VERSION 5.7 ;
BUSBITCHARS "[]" ;
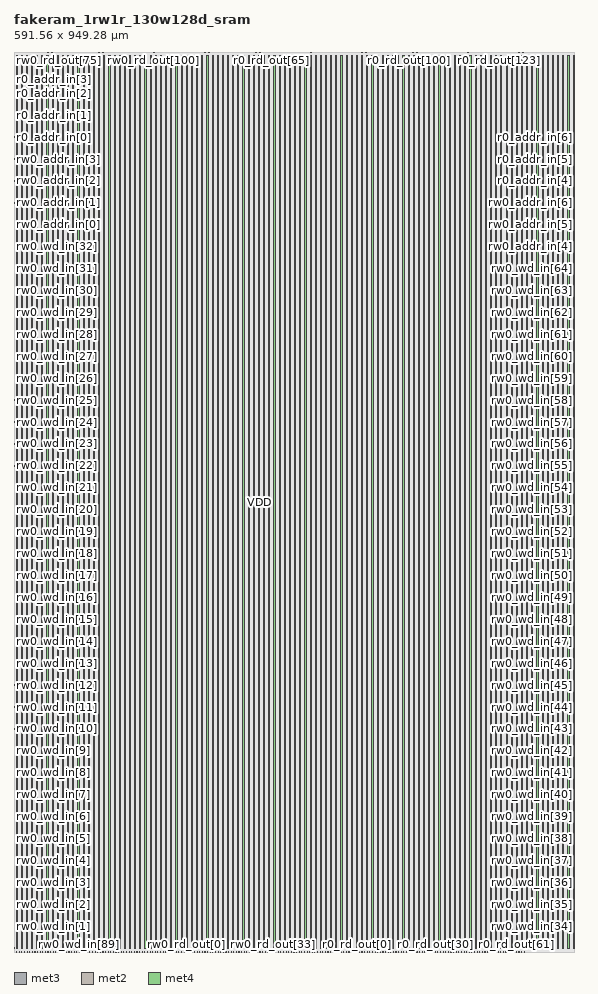
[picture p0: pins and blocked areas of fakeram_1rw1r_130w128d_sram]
MACRO fakeram_1rw1r_130w128d_sram
  FOREIGN fakeram_1rw1r_130w128d_sram 0 0 ;
  SYMMETRY X Y R90 ;
  SIZE 591.560 BY 949.280 ;
  CLASS BLOCK ;
  PIN rw0_wd_in[0]
    DIRECTION INPUT ;
    USE SIGNAL ;
    SHAPE ABUTMENT ;
    PORT
      LAYER met3 ;
      RECT 0.000 3.930 0.900 4.230 ;
    END
  END rw0_wd_in[0]
  PIN rw0_wd_in[1]
    DIRECTION INPUT ;
    USE SIGNAL ;
    SHAPE ABUTMENT ;
    PORT
      LAYER met3 ;
      RECT 0.000 27.050 0.900 27.350 ;
    END
  END rw0_wd_in[1]
  PIN rw0_wd_in[2]
    DIRECTION INPUT ;
    USE SIGNAL ;
    SHAPE ABUTMENT ;
    PORT
      LAYER met3 ;
      RECT 0.000 50.170 0.900 50.470 ;
    END
  END rw0_wd_in[2]
  PIN rw0_wd_in[3]
    DIRECTION INPUT ;
    USE SIGNAL ;
    SHAPE ABUTMENT ;
    PORT
      LAYER met3 ;
      RECT 0.000 73.290 0.900 73.590 ;
    END
  END rw0_wd_in[3]
  PIN rw0_wd_in[4]
    DIRECTION INPUT ;
    USE SIGNAL ;
    SHAPE ABUTMENT ;
    PORT
      LAYER met3 ;
      RECT 0.000 96.410 0.900 96.710 ;
    END
  END rw0_wd_in[4]
  PIN rw0_wd_in[5]
    DIRECTION INPUT ;
    USE SIGNAL ;
    SHAPE ABUTMENT ;
    PORT
      LAYER met3 ;
      RECT 0.000 119.530 0.900 119.830 ;
    END
  END rw0_wd_in[5]
  PIN rw0_wd_in[6]
    DIRECTION INPUT ;
    USE SIGNAL ;
    SHAPE ABUTMENT ;
    PORT
      LAYER met3 ;
      RECT 0.000 142.650 0.900 142.950 ;
    END
  END rw0_wd_in[6]
  PIN rw0_wd_in[7]
    DIRECTION INPUT ;
    USE SIGNAL ;
    SHAPE ABUTMENT ;
    PORT
      LAYER met3 ;
      RECT 0.000 165.770 0.900 166.070 ;
    END
  END rw0_wd_in[7]
  PIN rw0_wd_in[8]
    DIRECTION INPUT ;
    USE SIGNAL ;
    SHAPE ABUTMENT ;
    PORT
      LAYER met3 ;
      RECT 0.000 188.890 0.900 189.190 ;
    END
  END rw0_wd_in[8]
  PIN rw0_wd_in[9]
    DIRECTION INPUT ;
    USE SIGNAL ;
    SHAPE ABUTMENT ;
    PORT
      LAYER met3 ;
      RECT 0.000 212.010 0.900 212.310 ;
    END
  END rw0_wd_in[9]
  PIN rw0_wd_in[10]
    DIRECTION INPUT ;
    USE SIGNAL ;
    SHAPE ABUTMENT ;
    PORT
      LAYER met3 ;
      RECT 0.000 235.130 0.900 235.430 ;
    END
  END rw0_wd_in[10]
  PIN rw0_wd_in[11]
    DIRECTION INPUT ;
    USE SIGNAL ;
    SHAPE ABUTMENT ;
    PORT
      LAYER met3 ;
      RECT 0.000 258.250 0.900 258.550 ;
    END
  END rw0_wd_in[11]
  PIN rw0_wd_in[12]
    DIRECTION INPUT ;
    USE SIGNAL ;
    SHAPE ABUTMENT ;
    PORT
      LAYER met3 ;
      RECT 0.000 281.370 0.900 281.670 ;
    END
  END rw0_wd_in[12]
  PIN rw0_wd_in[13]
    DIRECTION INPUT ;
    USE SIGNAL ;
    SHAPE ABUTMENT ;
    PORT
      LAYER met3 ;
      RECT 0.000 304.490 0.900 304.790 ;
    END
  END rw0_wd_in[13]
  PIN rw0_wd_in[14]
    DIRECTION INPUT ;
    USE SIGNAL ;
    SHAPE ABUTMENT ;
    PORT
      LAYER met3 ;
      RECT 0.000 327.610 0.900 327.910 ;
    END
  END rw0_wd_in[14]
  PIN rw0_wd_in[15]
    DIRECTION INPUT ;
    USE SIGNAL ;
    SHAPE ABUTMENT ;
    PORT
      LAYER met3 ;
      RECT 0.000 350.730 0.900 351.030 ;
    END
  END rw0_wd_in[15]
  PIN rw0_wd_in[16]
    DIRECTION INPUT ;
    USE SIGNAL ;
    SHAPE ABUTMENT ;
    PORT
      LAYER met3 ;
      RECT 0.000 373.850 0.900 374.150 ;
    END
  END rw0_wd_in[16]
  PIN rw0_wd_in[17]
    DIRECTION INPUT ;
    USE SIGNAL ;
    SHAPE ABUTMENT ;
    PORT
      LAYER met3 ;
      RECT 0.000 396.970 0.900 397.270 ;
    END
  END rw0_wd_in[17]
  PIN rw0_wd_in[18]
    DIRECTION INPUT ;
    USE SIGNAL ;
    SHAPE ABUTMENT ;
    PORT
      LAYER met3 ;
      RECT 0.000 420.090 0.900 420.390 ;
    END
  END rw0_wd_in[18]
  PIN rw0_wd_in[19]
    DIRECTION INPUT ;
    USE SIGNAL ;
    SHAPE ABUTMENT ;
    PORT
      LAYER met3 ;
      RECT 0.000 443.210 0.900 443.510 ;
    END
  END rw0_wd_in[19]
  PIN rw0_wd_in[20]
    DIRECTION INPUT ;
    USE SIGNAL ;
    SHAPE ABUTMENT ;
    PORT
      LAYER met3 ;
      RECT 0.000 466.330 0.900 466.630 ;
    END
  END rw0_wd_in[20]
  PIN rw0_wd_in[21]
    DIRECTION INPUT ;
    USE SIGNAL ;
    SHAPE ABUTMENT ;
    PORT
      LAYER met3 ;
      RECT 0.000 489.450 0.900 489.750 ;
    END
  END rw0_wd_in[21]
  PIN rw0_wd_in[22]
    DIRECTION INPUT ;
    USE SIGNAL ;
    SHAPE ABUTMENT ;
    PORT
      LAYER met3 ;
      RECT 0.000 512.570 0.900 512.870 ;
    END
  END rw0_wd_in[22]
  PIN rw0_wd_in[23]
    DIRECTION INPUT ;
    USE SIGNAL ;
    SHAPE ABUTMENT ;
    PORT
      LAYER met3 ;
      RECT 0.000 535.690 0.900 535.990 ;
    END
  END rw0_wd_in[23]
  PIN rw0_wd_in[24]
    DIRECTION INPUT ;
    USE SIGNAL ;
    SHAPE ABUTMENT ;
    PORT
      LAYER met3 ;
      RECT 0.000 558.810 0.900 559.110 ;
    END
  END rw0_wd_in[24]
  PIN rw0_wd_in[25]
    DIRECTION INPUT ;
    USE SIGNAL ;
    SHAPE ABUTMENT ;
    PORT
      LAYER met3 ;
      RECT 0.000 581.930 0.900 582.230 ;
    END
  END rw0_wd_in[25]
  PIN rw0_wd_in[26]
    DIRECTION INPUT ;
    USE SIGNAL ;
    SHAPE ABUTMENT ;
    PORT
      LAYER met3 ;
      RECT 0.000 605.050 0.900 605.350 ;
    END
  END rw0_wd_in[26]
  PIN rw0_wd_in[27]
    DIRECTION INPUT ;
    USE SIGNAL ;
    SHAPE ABUTMENT ;
    PORT
      LAYER met3 ;
      RECT 0.000 628.170 0.900 628.470 ;
    END
  END rw0_wd_in[27]
  PIN rw0_wd_in[28]
    DIRECTION INPUT ;
    USE SIGNAL ;
    SHAPE ABUTMENT ;
    PORT
      LAYER met3 ;
      RECT 0.000 651.290 0.900 651.590 ;
    END
  END rw0_wd_in[28]
  PIN rw0_wd_in[29]
    DIRECTION INPUT ;
    USE SIGNAL ;
    SHAPE ABUTMENT ;
    PORT
      LAYER met3 ;
      RECT 0.000 674.410 0.900 674.710 ;
    END
  END rw0_wd_in[29]
  PIN rw0_wd_in[30]
    DIRECTION INPUT ;
    USE SIGNAL ;
    SHAPE ABUTMENT ;
    PORT
      LAYER met3 ;
      RECT 0.000 697.530 0.900 697.830 ;
    END
  END rw0_wd_in[30]
  PIN rw0_wd_in[31]
    DIRECTION INPUT ;
    USE SIGNAL ;
    SHAPE ABUTMENT ;
    PORT
      LAYER met3 ;
      RECT 0.000 720.650 0.900 720.950 ;
    END
  END rw0_wd_in[31]
  PIN rw0_wd_in[32]
    DIRECTION INPUT ;
    USE SIGNAL ;
    SHAPE ABUTMENT ;
    PORT
      LAYER met3 ;
      RECT 0.000 743.770 0.900 744.070 ;
    END
  END rw0_wd_in[32]
  PIN rw0_wd_in[33]
    DIRECTION INPUT ;
    USE SIGNAL ;
    SHAPE ABUTMENT ;
    PORT
      LAYER met3 ;
      RECT 590.660 3.930 591.560 4.230 ;
    END
  END rw0_wd_in[33]
  PIN rw0_wd_in[34]
    DIRECTION INPUT ;
    USE SIGNAL ;
    SHAPE ABUTMENT ;
    PORT
      LAYER met3 ;
      RECT 590.660 27.050 591.560 27.350 ;
    END
  END rw0_wd_in[34]
  PIN rw0_wd_in[35]
    DIRECTION INPUT ;
    USE SIGNAL ;
    SHAPE ABUTMENT ;
    PORT
      LAYER met3 ;
      RECT 590.660 50.170 591.560 50.470 ;
    END
  END rw0_wd_in[35]
  PIN rw0_wd_in[36]
    DIRECTION INPUT ;
    USE SIGNAL ;
    SHAPE ABUTMENT ;
    PORT
      LAYER met3 ;
      RECT 590.660 73.290 591.560 73.590 ;
    END
  END rw0_wd_in[36]
  PIN rw0_wd_in[37]
    DIRECTION INPUT ;
    USE SIGNAL ;
    SHAPE ABUTMENT ;
    PORT
      LAYER met3 ;
      RECT 590.660 96.410 591.560 96.710 ;
    END
  END rw0_wd_in[37]
  PIN rw0_wd_in[38]
    DIRECTION INPUT ;
    USE SIGNAL ;
    SHAPE ABUTMENT ;
    PORT
      LAYER met3 ;
      RECT 590.660 119.530 591.560 119.830 ;
    END
  END rw0_wd_in[38]
  PIN rw0_wd_in[39]
    DIRECTION INPUT ;
    USE SIGNAL ;
    SHAPE ABUTMENT ;
    PORT
      LAYER met3 ;
      RECT 590.660 142.650 591.560 142.950 ;
    END
  END rw0_wd_in[39]
  PIN rw0_wd_in[40]
    DIRECTION INPUT ;
    USE SIGNAL ;
    SHAPE ABUTMENT ;
    PORT
      LAYER met3 ;
      RECT 590.660 165.770 591.560 166.070 ;
    END
  END rw0_wd_in[40]
  PIN rw0_wd_in[41]
    DIRECTION INPUT ;
    USE SIGNAL ;
    SHAPE ABUTMENT ;
    PORT
      LAYER met3 ;
      RECT 590.660 188.890 591.560 189.190 ;
    END
  END rw0_wd_in[41]
  PIN rw0_wd_in[42]
    DIRECTION INPUT ;
    USE SIGNAL ;
    SHAPE ABUTMENT ;
    PORT
      LAYER met3 ;
      RECT 590.660 212.010 591.560 212.310 ;
    END
  END rw0_wd_in[42]
  PIN rw0_wd_in[43]
    DIRECTION INPUT ;
    USE SIGNAL ;
    SHAPE ABUTMENT ;
    PORT
      LAYER met3 ;
      RECT 590.660 235.130 591.560 235.430 ;
    END
  END rw0_wd_in[43]
  PIN rw0_wd_in[44]
    DIRECTION INPUT ;
    USE SIGNAL ;
    SHAPE ABUTMENT ;
    PORT
      LAYER met3 ;
      RECT 590.660 258.250 591.560 258.550 ;
    END
  END rw0_wd_in[44]
  PIN rw0_wd_in[45]
    DIRECTION INPUT ;
    USE SIGNAL ;
    SHAPE ABUTMENT ;
    PORT
      LAYER met3 ;
      RECT 590.660 281.370 591.560 281.670 ;
    END
  END rw0_wd_in[45]
  PIN rw0_wd_in[46]
    DIRECTION INPUT ;
    USE SIGNAL ;
    SHAPE ABUTMENT ;
    PORT
      LAYER met3 ;
      RECT 590.660 304.490 591.560 304.790 ;
    END
  END rw0_wd_in[46]
  PIN rw0_wd_in[47]
    DIRECTION INPUT ;
    USE SIGNAL ;
    SHAPE ABUTMENT ;
    PORT
      LAYER met3 ;
      RECT 590.660 327.610 591.560 327.910 ;
    END
  END rw0_wd_in[47]
  PIN rw0_wd_in[48]
    DIRECTION INPUT ;
    USE SIGNAL ;
    SHAPE ABUTMENT ;
    PORT
      LAYER met3 ;
      RECT 590.660 350.730 591.560 351.030 ;
    END
  END rw0_wd_in[48]
  PIN rw0_wd_in[49]
    DIRECTION INPUT ;
    USE SIGNAL ;
    SHAPE ABUTMENT ;
    PORT
      LAYER met3 ;
      RECT 590.660 373.850 591.560 374.150 ;
    END
  END rw0_wd_in[49]
  PIN rw0_wd_in[50]
    DIRECTION INPUT ;
    USE SIGNAL ;
    SHAPE ABUTMENT ;
    PORT
      LAYER met3 ;
      RECT 590.660 396.970 591.560 397.270 ;
    END
  END rw0_wd_in[50]
  PIN rw0_wd_in[51]
    DIRECTION INPUT ;
    USE SIGNAL ;
    SHAPE ABUTMENT ;
    PORT
      LAYER met3 ;
      RECT 590.660 420.090 591.560 420.390 ;
    END
  END rw0_wd_in[51]
  PIN rw0_wd_in[52]
    DIRECTION INPUT ;
    USE SIGNAL ;
    SHAPE ABUTMENT ;
    PORT
      LAYER met3 ;
      RECT 590.660 443.210 591.560 443.510 ;
    END
  END rw0_wd_in[52]
  PIN rw0_wd_in[53]
    DIRECTION INPUT ;
    USE SIGNAL ;
    SHAPE ABUTMENT ;
    PORT
      LAYER met3 ;
      RECT 590.660 466.330 591.560 466.630 ;
    END
  END rw0_wd_in[53]
  PIN rw0_wd_in[54]
    DIRECTION INPUT ;
    USE SIGNAL ;
    SHAPE ABUTMENT ;
    PORT
      LAYER met3 ;
      RECT 590.660 489.450 591.560 489.750 ;
    END
  END rw0_wd_in[54]
  PIN rw0_wd_in[55]
    DIRECTION INPUT ;
    USE SIGNAL ;
    SHAPE ABUTMENT ;
    PORT
      LAYER met3 ;
      RECT 590.660 512.570 591.560 512.870 ;
    END
  END rw0_wd_in[55]
  PIN rw0_wd_in[56]
    DIRECTION INPUT ;
    USE SIGNAL ;
    SHAPE ABUTMENT ;
    PORT
      LAYER met3 ;
      RECT 590.660 535.690 591.560 535.990 ;
    END
  END rw0_wd_in[56]
  PIN rw0_wd_in[57]
    DIRECTION INPUT ;
    USE SIGNAL ;
    SHAPE ABUTMENT ;
    PORT
      LAYER met3 ;
      RECT 590.660 558.810 591.560 559.110 ;
    END
  END rw0_wd_in[57]
  PIN rw0_wd_in[58]
    DIRECTION INPUT ;
    USE SIGNAL ;
    SHAPE ABUTMENT ;
    PORT
      LAYER met3 ;
      RECT 590.660 581.930 591.560 582.230 ;
    END
  END rw0_wd_in[58]
  PIN rw0_wd_in[59]
    DIRECTION INPUT ;
    USE SIGNAL ;
    SHAPE ABUTMENT ;
    PORT
      LAYER met3 ;
      RECT 590.660 605.050 591.560 605.350 ;
    END
  END rw0_wd_in[59]
  PIN rw0_wd_in[60]
    DIRECTION INPUT ;
    USE SIGNAL ;
    SHAPE ABUTMENT ;
    PORT
      LAYER met3 ;
      RECT 590.660 628.170 591.560 628.470 ;
    END
  END rw0_wd_in[60]
  PIN rw0_wd_in[61]
    DIRECTION INPUT ;
    USE SIGNAL ;
    SHAPE ABUTMENT ;
    PORT
      LAYER met3 ;
      RECT 590.660 651.290 591.560 651.590 ;
    END
  END rw0_wd_in[61]
  PIN rw0_wd_in[62]
    DIRECTION INPUT ;
    USE SIGNAL ;
    SHAPE ABUTMENT ;
    PORT
      LAYER met3 ;
      RECT 590.660 674.410 591.560 674.710 ;
    END
  END rw0_wd_in[62]
  PIN rw0_wd_in[63]
    DIRECTION INPUT ;
    USE SIGNAL ;
    SHAPE ABUTMENT ;
    PORT
      LAYER met3 ;
      RECT 590.660 697.530 591.560 697.830 ;
    END
  END rw0_wd_in[63]
  PIN rw0_wd_in[64]
    DIRECTION INPUT ;
    USE SIGNAL ;
    SHAPE ABUTMENT ;
    PORT
      LAYER met3 ;
      RECT 590.660 720.650 591.560 720.950 ;
    END
  END rw0_wd_in[64]
  PIN rw0_wd_in[65]
    DIRECTION INPUT ;
    USE SIGNAL ;
    SHAPE ABUTMENT ;
    PORT
      LAYER met2 ;
      RECT 2.690 0.000 2.830 0.420 ;
    END
  END rw0_wd_in[65]
  PIN rw0_wd_in[66]
    DIRECTION INPUT ;
    USE SIGNAL ;
    SHAPE ABUTMENT ;
    PORT
      LAYER met2 ;
      RECT 5.450 0.000 5.590 0.420 ;
    END
  END rw0_wd_in[66]
  PIN rw0_wd_in[67]
    DIRECTION INPUT ;
    USE SIGNAL ;
    SHAPE ABUTMENT ;
    PORT
      LAYER met2 ;
      RECT 8.210 0.000 8.350 0.420 ;
    END
  END rw0_wd_in[67]
  PIN rw0_wd_in[68]
    DIRECTION INPUT ;
    USE SIGNAL ;
    SHAPE ABUTMENT ;
    PORT
      LAYER met2 ;
      RECT 10.970 0.000 11.110 0.420 ;
    END
  END rw0_wd_in[68]
  PIN rw0_wd_in[69]
    DIRECTION INPUT ;
    USE SIGNAL ;
    SHAPE ABUTMENT ;
    PORT
      LAYER met2 ;
      RECT 13.730 0.000 13.870 0.420 ;
    END
  END rw0_wd_in[69]
  PIN rw0_wd_in[70]
    DIRECTION INPUT ;
    USE SIGNAL ;
    SHAPE ABUTMENT ;
    PORT
      LAYER met2 ;
      RECT 16.490 0.000 16.630 0.420 ;
    END
  END rw0_wd_in[70]
  PIN rw0_wd_in[71]
    DIRECTION INPUT ;
    USE SIGNAL ;
    SHAPE ABUTMENT ;
    PORT
      LAYER met2 ;
      RECT 19.250 0.000 19.390 0.420 ;
    END
  END rw0_wd_in[71]
  PIN rw0_wd_in[72]
    DIRECTION INPUT ;
    USE SIGNAL ;
    SHAPE ABUTMENT ;
    PORT
      LAYER met2 ;
      RECT 22.010 0.000 22.150 0.420 ;
    END
  END rw0_wd_in[72]
  PIN rw0_wd_in[73]
    DIRECTION INPUT ;
    USE SIGNAL ;
    SHAPE ABUTMENT ;
    PORT
      LAYER met2 ;
      RECT 24.770 0.000 24.910 0.420 ;
    END
  END rw0_wd_in[73]
  PIN rw0_wd_in[74]
    DIRECTION INPUT ;
    USE SIGNAL ;
    SHAPE ABUTMENT ;
    PORT
      LAYER met2 ;
      RECT 27.530 0.000 27.670 0.420 ;
    END
  END rw0_wd_in[74]
  PIN rw0_wd_in[75]
    DIRECTION INPUT ;
    USE SIGNAL ;
    SHAPE ABUTMENT ;
    PORT
      LAYER met2 ;
      RECT 30.290 0.000 30.430 0.420 ;
    END
  END rw0_wd_in[75]
  PIN rw0_wd_in[76]
    DIRECTION INPUT ;
    USE SIGNAL ;
    SHAPE ABUTMENT ;
    PORT
      LAYER met2 ;
      RECT 33.050 0.000 33.190 0.420 ;
    END
  END rw0_wd_in[76]
  PIN rw0_wd_in[77]
    DIRECTION INPUT ;
    USE SIGNAL ;
    SHAPE ABUTMENT ;
    PORT
      LAYER met2 ;
      RECT 35.810 0.000 35.950 0.420 ;
    END
  END rw0_wd_in[77]
  PIN rw0_wd_in[78]
    DIRECTION INPUT ;
    USE SIGNAL ;
    SHAPE ABUTMENT ;
    PORT
      LAYER met2 ;
      RECT 38.570 0.000 38.710 0.420 ;
    END
  END rw0_wd_in[78]
  PIN rw0_wd_in[79]
    DIRECTION INPUT ;
    USE SIGNAL ;
    SHAPE ABUTMENT ;
    PORT
      LAYER met2 ;
      RECT 41.330 0.000 41.470 0.420 ;
    END
  END rw0_wd_in[79]
  PIN rw0_wd_in[80]
    DIRECTION INPUT ;
    USE SIGNAL ;
    SHAPE ABUTMENT ;
    PORT
      LAYER met2 ;
      RECT 44.090 0.000 44.230 0.420 ;
    END
  END rw0_wd_in[80]
  PIN rw0_wd_in[81]
    DIRECTION INPUT ;
    USE SIGNAL ;
    SHAPE ABUTMENT ;
    PORT
      LAYER met2 ;
      RECT 46.850 0.000 46.990 0.420 ;
    END
  END rw0_wd_in[81]
  PIN rw0_wd_in[82]
    DIRECTION INPUT ;
    USE SIGNAL ;
    SHAPE ABUTMENT ;
    PORT
      LAYER met2 ;
      RECT 49.610 0.000 49.750 0.420 ;
    END
  END rw0_wd_in[82]
  PIN rw0_wd_in[83]
    DIRECTION INPUT ;
    USE SIGNAL ;
    SHAPE ABUTMENT ;
    PORT
      LAYER met2 ;
      RECT 52.370 0.000 52.510 0.420 ;
    END
  END rw0_wd_in[83]
  PIN rw0_wd_in[84]
    DIRECTION INPUT ;
    USE SIGNAL ;
    SHAPE ABUTMENT ;
    PORT
      LAYER met2 ;
      RECT 55.130 0.000 55.270 0.420 ;
    END
  END rw0_wd_in[84]
  PIN rw0_wd_in[85]
    DIRECTION INPUT ;
    USE SIGNAL ;
    SHAPE ABUTMENT ;
    PORT
      LAYER met2 ;
      RECT 57.890 0.000 58.030 0.420 ;
    END
  END rw0_wd_in[85]
  PIN rw0_wd_in[86]
    DIRECTION INPUT ;
    USE SIGNAL ;
    SHAPE ABUTMENT ;
    PORT
      LAYER met2 ;
      RECT 60.650 0.000 60.790 0.420 ;
    END
  END rw0_wd_in[86]
  PIN rw0_wd_in[87]
    DIRECTION INPUT ;
    USE SIGNAL ;
    SHAPE ABUTMENT ;
    PORT
      LAYER met2 ;
      RECT 63.410 0.000 63.550 0.420 ;
    END
  END rw0_wd_in[87]
  PIN rw0_wd_in[88]
    DIRECTION INPUT ;
    USE SIGNAL ;
    SHAPE ABUTMENT ;
    PORT
      LAYER met2 ;
      RECT 66.170 0.000 66.310 0.420 ;
    END
  END rw0_wd_in[88]
  PIN rw0_wd_in[89]
    DIRECTION INPUT ;
    USE SIGNAL ;
    SHAPE ABUTMENT ;
    PORT
      LAYER met2 ;
      RECT 68.930 0.000 69.070 0.420 ;
    END
  END rw0_wd_in[89]
  PIN rw0_wd_in[90]
    DIRECTION INPUT ;
    USE SIGNAL ;
    SHAPE ABUTMENT ;
    PORT
      LAYER met2 ;
      RECT 71.690 0.000 71.830 0.420 ;
    END
  END rw0_wd_in[90]
  PIN rw0_wd_in[91]
    DIRECTION INPUT ;
    USE SIGNAL ;
    SHAPE ABUTMENT ;
    PORT
      LAYER met2 ;
      RECT 74.450 0.000 74.590 0.420 ;
    END
  END rw0_wd_in[91]
  PIN rw0_wd_in[92]
    DIRECTION INPUT ;
    USE SIGNAL ;
    SHAPE ABUTMENT ;
    PORT
      LAYER met2 ;
      RECT 77.210 0.000 77.350 0.420 ;
    END
  END rw0_wd_in[92]
  PIN rw0_wd_in[93]
    DIRECTION INPUT ;
    USE SIGNAL ;
    SHAPE ABUTMENT ;
    PORT
      LAYER met2 ;
      RECT 79.970 0.000 80.110 0.420 ;
    END
  END rw0_wd_in[93]
  PIN rw0_wd_in[94]
    DIRECTION INPUT ;
    USE SIGNAL ;
    SHAPE ABUTMENT ;
    PORT
      LAYER met2 ;
      RECT 82.730 0.000 82.870 0.420 ;
    END
  END rw0_wd_in[94]
  PIN rw0_wd_in[95]
    DIRECTION INPUT ;
    USE SIGNAL ;
    SHAPE ABUTMENT ;
    PORT
      LAYER met2 ;
      RECT 85.490 0.000 85.630 0.420 ;
    END
  END rw0_wd_in[95]
  PIN rw0_wd_in[96]
    DIRECTION INPUT ;
    USE SIGNAL ;
    SHAPE ABUTMENT ;
    PORT
      LAYER met2 ;
      RECT 88.250 0.000 88.390 0.420 ;
    END
  END rw0_wd_in[96]
  PIN rw0_wd_in[97]
    DIRECTION INPUT ;
    USE SIGNAL ;
    SHAPE ABUTMENT ;
    PORT
      LAYER met2 ;
      RECT 91.010 0.000 91.150 0.420 ;
    END
  END rw0_wd_in[97]
  PIN rw0_wd_in[98]
    DIRECTION INPUT ;
    USE SIGNAL ;
    SHAPE ABUTMENT ;
    PORT
      LAYER met2 ;
      RECT 93.770 0.000 93.910 0.420 ;
    END
  END rw0_wd_in[98]
  PIN rw0_wd_in[99]
    DIRECTION INPUT ;
    USE SIGNAL ;
    SHAPE ABUTMENT ;
    PORT
      LAYER met2 ;
      RECT 96.530 0.000 96.670 0.420 ;
    END
  END rw0_wd_in[99]
  PIN rw0_wd_in[100]
    DIRECTION INPUT ;
    USE SIGNAL ;
    SHAPE ABUTMENT ;
    PORT
      LAYER met2 ;
      RECT 99.290 0.000 99.430 0.420 ;
    END
  END rw0_wd_in[100]
  PIN rw0_wd_in[101]
    DIRECTION INPUT ;
    USE SIGNAL ;
    SHAPE ABUTMENT ;
    PORT
      LAYER met2 ;
      RECT 102.050 0.000 102.190 0.420 ;
    END
  END rw0_wd_in[101]
  PIN rw0_wd_in[102]
    DIRECTION INPUT ;
    USE SIGNAL ;
    SHAPE ABUTMENT ;
    PORT
      LAYER met2 ;
      RECT 104.810 0.000 104.950 0.420 ;
    END
  END rw0_wd_in[102]
  PIN rw0_wd_in[103]
    DIRECTION INPUT ;
    USE SIGNAL ;
    SHAPE ABUTMENT ;
    PORT
      LAYER met2 ;
      RECT 107.570 0.000 107.710 0.420 ;
    END
  END rw0_wd_in[103]
  PIN rw0_wd_in[104]
    DIRECTION INPUT ;
    USE SIGNAL ;
    SHAPE ABUTMENT ;
    PORT
      LAYER met2 ;
      RECT 110.330 0.000 110.470 0.420 ;
    END
  END rw0_wd_in[104]
  PIN rw0_wd_in[105]
    DIRECTION INPUT ;
    USE SIGNAL ;
    SHAPE ABUTMENT ;
    PORT
      LAYER met2 ;
      RECT 113.090 0.000 113.230 0.420 ;
    END
  END rw0_wd_in[105]
  PIN rw0_wd_in[106]
    DIRECTION INPUT ;
    USE SIGNAL ;
    SHAPE ABUTMENT ;
    PORT
      LAYER met2 ;
      RECT 115.850 0.000 115.990 0.420 ;
    END
  END rw0_wd_in[106]
  PIN rw0_wd_in[107]
    DIRECTION INPUT ;
    USE SIGNAL ;
    SHAPE ABUTMENT ;
    PORT
      LAYER met2 ;
      RECT 118.610 0.000 118.750 0.420 ;
    END
  END rw0_wd_in[107]
  PIN rw0_wd_in[108]
    DIRECTION INPUT ;
    USE SIGNAL ;
    SHAPE ABUTMENT ;
    PORT
      LAYER met2 ;
      RECT 121.370 0.000 121.510 0.420 ;
    END
  END rw0_wd_in[108]
  PIN rw0_wd_in[109]
    DIRECTION INPUT ;
    USE SIGNAL ;
    SHAPE ABUTMENT ;
    PORT
      LAYER met2 ;
      RECT 124.130 0.000 124.270 0.420 ;
    END
  END rw0_wd_in[109]
  PIN rw0_wd_in[110]
    DIRECTION INPUT ;
    USE SIGNAL ;
    SHAPE ABUTMENT ;
    PORT
      LAYER met2 ;
      RECT 126.890 0.000 127.030 0.420 ;
    END
  END rw0_wd_in[110]
  PIN rw0_wd_in[111]
    DIRECTION INPUT ;
    USE SIGNAL ;
    SHAPE ABUTMENT ;
    PORT
      LAYER met2 ;
      RECT 129.650 0.000 129.790 0.420 ;
    END
  END rw0_wd_in[111]
  PIN rw0_wd_in[112]
    DIRECTION INPUT ;
    USE SIGNAL ;
    SHAPE ABUTMENT ;
    PORT
      LAYER met2 ;
      RECT 132.410 0.000 132.550 0.420 ;
    END
  END rw0_wd_in[112]
  PIN rw0_wd_in[113]
    DIRECTION INPUT ;
    USE SIGNAL ;
    SHAPE ABUTMENT ;
    PORT
      LAYER met2 ;
      RECT 135.170 0.000 135.310 0.420 ;
    END
  END rw0_wd_in[113]
  PIN rw0_wd_in[114]
    DIRECTION INPUT ;
    USE SIGNAL ;
    SHAPE ABUTMENT ;
    PORT
      LAYER met2 ;
      RECT 137.930 0.000 138.070 0.420 ;
    END
  END rw0_wd_in[114]
  PIN rw0_wd_in[115]
    DIRECTION INPUT ;
    USE SIGNAL ;
    SHAPE ABUTMENT ;
    PORT
      LAYER met2 ;
      RECT 140.690 0.000 140.830 0.420 ;
    END
  END rw0_wd_in[115]
  PIN rw0_wd_in[116]
    DIRECTION INPUT ;
    USE SIGNAL ;
    SHAPE ABUTMENT ;
    PORT
      LAYER met2 ;
      RECT 143.450 0.000 143.590 0.420 ;
    END
  END rw0_wd_in[116]
  PIN rw0_wd_in[117]
    DIRECTION INPUT ;
    USE SIGNAL ;
    SHAPE ABUTMENT ;
    PORT
      LAYER met2 ;
      RECT 146.210 0.000 146.350 0.420 ;
    END
  END rw0_wd_in[117]
  PIN rw0_wd_in[118]
    DIRECTION INPUT ;
    USE SIGNAL ;
    SHAPE ABUTMENT ;
    PORT
      LAYER met2 ;
      RECT 148.970 0.000 149.110 0.420 ;
    END
  END rw0_wd_in[118]
  PIN rw0_wd_in[119]
    DIRECTION INPUT ;
    USE SIGNAL ;
    SHAPE ABUTMENT ;
    PORT
      LAYER met2 ;
      RECT 151.730 0.000 151.870 0.420 ;
    END
  END rw0_wd_in[119]
  PIN rw0_wd_in[120]
    DIRECTION INPUT ;
    USE SIGNAL ;
    SHAPE ABUTMENT ;
    PORT
      LAYER met2 ;
      RECT 154.490 0.000 154.630 0.420 ;
    END
  END rw0_wd_in[120]
  PIN rw0_wd_in[121]
    DIRECTION INPUT ;
    USE SIGNAL ;
    SHAPE ABUTMENT ;
    PORT
      LAYER met2 ;
      RECT 157.250 0.000 157.390 0.420 ;
    END
  END rw0_wd_in[121]
  PIN rw0_wd_in[122]
    DIRECTION INPUT ;
    USE SIGNAL ;
    SHAPE ABUTMENT ;
    PORT
      LAYER met2 ;
      RECT 160.010 0.000 160.150 0.420 ;
    END
  END rw0_wd_in[122]
  PIN rw0_wd_in[123]
    DIRECTION INPUT ;
    USE SIGNAL ;
    SHAPE ABUTMENT ;
    PORT
      LAYER met2 ;
      RECT 162.770 0.000 162.910 0.420 ;
    END
  END rw0_wd_in[123]
  PIN rw0_wd_in[124]
    DIRECTION INPUT ;
    USE SIGNAL ;
    SHAPE ABUTMENT ;
    PORT
      LAYER met2 ;
      RECT 165.530 0.000 165.670 0.420 ;
    END
  END rw0_wd_in[124]
  PIN rw0_wd_in[125]
    DIRECTION INPUT ;
    USE SIGNAL ;
    SHAPE ABUTMENT ;
    PORT
      LAYER met2 ;
      RECT 168.290 0.000 168.430 0.420 ;
    END
  END rw0_wd_in[125]
  PIN rw0_wd_in[126]
    DIRECTION INPUT ;
    USE SIGNAL ;
    SHAPE ABUTMENT ;
    PORT
      LAYER met2 ;
      RECT 171.050 0.000 171.190 0.420 ;
    END
  END rw0_wd_in[126]
  PIN rw0_wd_in[127]
    DIRECTION INPUT ;
    USE SIGNAL ;
    SHAPE ABUTMENT ;
    PORT
      LAYER met2 ;
      RECT 173.810 0.000 173.950 0.420 ;
    END
  END rw0_wd_in[127]
  PIN rw0_wd_in[128]
    DIRECTION INPUT ;
    USE SIGNAL ;
    SHAPE ABUTMENT ;
    PORT
      LAYER met2 ;
      RECT 176.570 0.000 176.710 0.420 ;
    END
  END rw0_wd_in[128]
  PIN rw0_wd_in[129]
    DIRECTION INPUT ;
    USE SIGNAL ;
    SHAPE ABUTMENT ;
    PORT
      LAYER met2 ;
      RECT 179.330 0.000 179.470 0.420 ;
    END
  END rw0_wd_in[129]
  PIN rw0_rd_out[0]
    DIRECTION OUTPUT ;
    USE SIGNAL ;
    SHAPE ABUTMENT ;
    PORT
      LAYER met2 ;
      RECT 182.090 0.000 182.230 0.420 ;
    END
  END rw0_rd_out[0]
  PIN rw0_rd_out[1]
    DIRECTION OUTPUT ;
    USE SIGNAL ;
    SHAPE ABUTMENT ;
    PORT
      LAYER met2 ;
      RECT 184.850 0.000 184.990 0.420 ;
    END
  END rw0_rd_out[1]
  PIN rw0_rd_out[2]
    DIRECTION OUTPUT ;
    USE SIGNAL ;
    SHAPE ABUTMENT ;
    PORT
      LAYER met2 ;
      RECT 187.610 0.000 187.750 0.420 ;
    END
  END rw0_rd_out[2]
  PIN rw0_rd_out[3]
    DIRECTION OUTPUT ;
    USE SIGNAL ;
    SHAPE ABUTMENT ;
    PORT
      LAYER met2 ;
      RECT 190.370 0.000 190.510 0.420 ;
    END
  END rw0_rd_out[3]
  PIN rw0_rd_out[4]
    DIRECTION OUTPUT ;
    USE SIGNAL ;
    SHAPE ABUTMENT ;
    PORT
      LAYER met2 ;
      RECT 193.130 0.000 193.270 0.420 ;
    END
  END rw0_rd_out[4]
  PIN rw0_rd_out[5]
    DIRECTION OUTPUT ;
    USE SIGNAL ;
    SHAPE ABUTMENT ;
    PORT
      LAYER met2 ;
      RECT 195.890 0.000 196.030 0.420 ;
    END
  END rw0_rd_out[5]
  PIN rw0_rd_out[6]
    DIRECTION OUTPUT ;
    USE SIGNAL ;
    SHAPE ABUTMENT ;
    PORT
      LAYER met2 ;
      RECT 198.650 0.000 198.790 0.420 ;
    END
  END rw0_rd_out[6]
  PIN rw0_rd_out[7]
    DIRECTION OUTPUT ;
    USE SIGNAL ;
    SHAPE ABUTMENT ;
    PORT
      LAYER met2 ;
      RECT 201.410 0.000 201.550 0.420 ;
    END
  END rw0_rd_out[7]
  PIN rw0_rd_out[8]
    DIRECTION OUTPUT ;
    USE SIGNAL ;
    SHAPE ABUTMENT ;
    PORT
      LAYER met2 ;
      RECT 204.170 0.000 204.310 0.420 ;
    END
  END rw0_rd_out[8]
  PIN rw0_rd_out[9]
    DIRECTION OUTPUT ;
    USE SIGNAL ;
    SHAPE ABUTMENT ;
    PORT
      LAYER met2 ;
      RECT 206.930 0.000 207.070 0.420 ;
    END
  END rw0_rd_out[9]
  PIN rw0_rd_out[10]
    DIRECTION OUTPUT ;
    USE SIGNAL ;
    SHAPE ABUTMENT ;
    PORT
      LAYER met2 ;
      RECT 209.690 0.000 209.830 0.420 ;
    END
  END rw0_rd_out[10]
  PIN rw0_rd_out[11]
    DIRECTION OUTPUT ;
    USE SIGNAL ;
    SHAPE ABUTMENT ;
    PORT
      LAYER met2 ;
      RECT 212.450 0.000 212.590 0.420 ;
    END
  END rw0_rd_out[11]
  PIN rw0_rd_out[12]
    DIRECTION OUTPUT ;
    USE SIGNAL ;
    SHAPE ABUTMENT ;
    PORT
      LAYER met2 ;
      RECT 215.210 0.000 215.350 0.420 ;
    END
  END rw0_rd_out[12]
  PIN rw0_rd_out[13]
    DIRECTION OUTPUT ;
    USE SIGNAL ;
    SHAPE ABUTMENT ;
    PORT
      LAYER met2 ;
      RECT 217.970 0.000 218.110 0.420 ;
    END
  END rw0_rd_out[13]
  PIN rw0_rd_out[14]
    DIRECTION OUTPUT ;
    USE SIGNAL ;
    SHAPE ABUTMENT ;
    PORT
      LAYER met2 ;
      RECT 220.730 0.000 220.870 0.420 ;
    END
  END rw0_rd_out[14]
  PIN rw0_rd_out[15]
    DIRECTION OUTPUT ;
    USE SIGNAL ;
    SHAPE ABUTMENT ;
    PORT
      LAYER met2 ;
      RECT 223.490 0.000 223.630 0.420 ;
    END
  END rw0_rd_out[15]
  PIN rw0_rd_out[16]
    DIRECTION OUTPUT ;
    USE SIGNAL ;
    SHAPE ABUTMENT ;
    PORT
      LAYER met2 ;
      RECT 226.250 0.000 226.390 0.420 ;
    END
  END rw0_rd_out[16]
  PIN rw0_rd_out[17]
    DIRECTION OUTPUT ;
    USE SIGNAL ;
    SHAPE ABUTMENT ;
    PORT
      LAYER met2 ;
      RECT 229.010 0.000 229.150 0.420 ;
    END
  END rw0_rd_out[17]
  PIN rw0_rd_out[18]
    DIRECTION OUTPUT ;
    USE SIGNAL ;
    SHAPE ABUTMENT ;
    PORT
      LAYER met2 ;
      RECT 231.770 0.000 231.910 0.420 ;
    END
  END rw0_rd_out[18]
  PIN rw0_rd_out[19]
    DIRECTION OUTPUT ;
    USE SIGNAL ;
    SHAPE ABUTMENT ;
    PORT
      LAYER met2 ;
      RECT 234.530 0.000 234.670 0.420 ;
    END
  END rw0_rd_out[19]
  PIN rw0_rd_out[20]
    DIRECTION OUTPUT ;
    USE SIGNAL ;
    SHAPE ABUTMENT ;
    PORT
      LAYER met2 ;
      RECT 237.290 0.000 237.430 0.420 ;
    END
  END rw0_rd_out[20]
  PIN rw0_rd_out[21]
    DIRECTION OUTPUT ;
    USE SIGNAL ;
    SHAPE ABUTMENT ;
    PORT
      LAYER met2 ;
      RECT 240.050 0.000 240.190 0.420 ;
    END
  END rw0_rd_out[21]
  PIN rw0_rd_out[22]
    DIRECTION OUTPUT ;
    USE SIGNAL ;
    SHAPE ABUTMENT ;
    PORT
      LAYER met2 ;
      RECT 242.810 0.000 242.950 0.420 ;
    END
  END rw0_rd_out[22]
  PIN rw0_rd_out[23]
    DIRECTION OUTPUT ;
    USE SIGNAL ;
    SHAPE ABUTMENT ;
    PORT
      LAYER met2 ;
      RECT 245.570 0.000 245.710 0.420 ;
    END
  END rw0_rd_out[23]
  PIN rw0_rd_out[24]
    DIRECTION OUTPUT ;
    USE SIGNAL ;
    SHAPE ABUTMENT ;
    PORT
      LAYER met2 ;
      RECT 248.330 0.000 248.470 0.420 ;
    END
  END rw0_rd_out[24]
  PIN rw0_rd_out[25]
    DIRECTION OUTPUT ;
    USE SIGNAL ;
    SHAPE ABUTMENT ;
    PORT
      LAYER met2 ;
      RECT 251.090 0.000 251.230 0.420 ;
    END
  END rw0_rd_out[25]
  PIN rw0_rd_out[26]
    DIRECTION OUTPUT ;
    USE SIGNAL ;
    SHAPE ABUTMENT ;
    PORT
      LAYER met2 ;
      RECT 253.850 0.000 253.990 0.420 ;
    END
  END rw0_rd_out[26]
  PIN rw0_rd_out[27]
    DIRECTION OUTPUT ;
    USE SIGNAL ;
    SHAPE ABUTMENT ;
    PORT
      LAYER met2 ;
      RECT 256.610 0.000 256.750 0.420 ;
    END
  END rw0_rd_out[27]
  PIN rw0_rd_out[28]
    DIRECTION OUTPUT ;
    USE SIGNAL ;
    SHAPE ABUTMENT ;
    PORT
      LAYER met2 ;
      RECT 259.370 0.000 259.510 0.420 ;
    END
  END rw0_rd_out[28]
  PIN rw0_rd_out[29]
    DIRECTION OUTPUT ;
    USE SIGNAL ;
    SHAPE ABUTMENT ;
    PORT
      LAYER met2 ;
      RECT 262.130 0.000 262.270 0.420 ;
    END
  END rw0_rd_out[29]
  PIN rw0_rd_out[30]
    DIRECTION OUTPUT ;
    USE SIGNAL ;
    SHAPE ABUTMENT ;
    PORT
      LAYER met2 ;
      RECT 264.890 0.000 265.030 0.420 ;
    END
  END rw0_rd_out[30]
  PIN rw0_rd_out[31]
    DIRECTION OUTPUT ;
    USE SIGNAL ;
    SHAPE ABUTMENT ;
    PORT
      LAYER met2 ;
      RECT 267.650 0.000 267.790 0.420 ;
    END
  END rw0_rd_out[31]
  PIN rw0_rd_out[32]
    DIRECTION OUTPUT ;
    USE SIGNAL ;
    SHAPE ABUTMENT ;
    PORT
      LAYER met2 ;
      RECT 270.410 0.000 270.550 0.420 ;
    END
  END rw0_rd_out[32]
  PIN rw0_rd_out[33]
    DIRECTION OUTPUT ;
    USE SIGNAL ;
    SHAPE ABUTMENT ;
    PORT
      LAYER met2 ;
      RECT 273.170 0.000 273.310 0.420 ;
    END
  END rw0_rd_out[33]
  PIN rw0_rd_out[34]
    DIRECTION OUTPUT ;
    USE SIGNAL ;
    SHAPE ABUTMENT ;
    PORT
      LAYER met2 ;
      RECT 275.930 0.000 276.070 0.420 ;
    END
  END rw0_rd_out[34]
  PIN rw0_rd_out[35]
    DIRECTION OUTPUT ;
    USE SIGNAL ;
    SHAPE ABUTMENT ;
    PORT
      LAYER met2 ;
      RECT 278.690 0.000 278.830 0.420 ;
    END
  END rw0_rd_out[35]
  PIN rw0_rd_out[36]
    DIRECTION OUTPUT ;
    USE SIGNAL ;
    SHAPE ABUTMENT ;
    PORT
      LAYER met2 ;
      RECT 281.450 0.000 281.590 0.420 ;
    END
  END rw0_rd_out[36]
  PIN rw0_rd_out[37]
    DIRECTION OUTPUT ;
    USE SIGNAL ;
    SHAPE ABUTMENT ;
    PORT
      LAYER met2 ;
      RECT 284.210 0.000 284.350 0.420 ;
    END
  END rw0_rd_out[37]
  PIN rw0_rd_out[38]
    DIRECTION OUTPUT ;
    USE SIGNAL ;
    SHAPE ABUTMENT ;
    PORT
      LAYER met2 ;
      RECT 286.970 0.000 287.110 0.420 ;
    END
  END rw0_rd_out[38]
  PIN rw0_rd_out[39]
    DIRECTION OUTPUT ;
    USE SIGNAL ;
    SHAPE ABUTMENT ;
    PORT
      LAYER met2 ;
      RECT 289.730 0.000 289.870 0.420 ;
    END
  END rw0_rd_out[39]
  PIN rw0_rd_out[40]
    DIRECTION OUTPUT ;
    USE SIGNAL ;
    SHAPE ABUTMENT ;
    PORT
      LAYER met2 ;
      RECT 292.490 0.000 292.630 0.420 ;
    END
  END rw0_rd_out[40]
  PIN rw0_rd_out[41]
    DIRECTION OUTPUT ;
    USE SIGNAL ;
    SHAPE ABUTMENT ;
    PORT
      LAYER met2 ;
      RECT 295.250 0.000 295.390 0.420 ;
    END
  END rw0_rd_out[41]
  PIN rw0_rd_out[42]
    DIRECTION OUTPUT ;
    USE SIGNAL ;
    SHAPE ABUTMENT ;
    PORT
      LAYER met2 ;
      RECT 298.010 0.000 298.150 0.420 ;
    END
  END rw0_rd_out[42]
  PIN rw0_rd_out[43]
    DIRECTION OUTPUT ;
    USE SIGNAL ;
    SHAPE ABUTMENT ;
    PORT
      LAYER met2 ;
      RECT 300.770 0.000 300.910 0.420 ;
    END
  END rw0_rd_out[43]
  PIN rw0_rd_out[44]
    DIRECTION OUTPUT ;
    USE SIGNAL ;
    SHAPE ABUTMENT ;
    PORT
      LAYER met2 ;
      RECT 303.530 0.000 303.670 0.420 ;
    END
  END rw0_rd_out[44]
  PIN rw0_rd_out[45]
    DIRECTION OUTPUT ;
    USE SIGNAL ;
    SHAPE ABUTMENT ;
    PORT
      LAYER met2 ;
      RECT 306.290 0.000 306.430 0.420 ;
    END
  END rw0_rd_out[45]
  PIN rw0_rd_out[46]
    DIRECTION OUTPUT ;
    USE SIGNAL ;
    SHAPE ABUTMENT ;
    PORT
      LAYER met2 ;
      RECT 309.050 0.000 309.190 0.420 ;
    END
  END rw0_rd_out[46]
  PIN rw0_rd_out[47]
    DIRECTION OUTPUT ;
    USE SIGNAL ;
    SHAPE ABUTMENT ;
    PORT
      LAYER met2 ;
      RECT 311.810 0.000 311.950 0.420 ;
    END
  END rw0_rd_out[47]
  PIN rw0_rd_out[48]
    DIRECTION OUTPUT ;
    USE SIGNAL ;
    SHAPE ABUTMENT ;
    PORT
      LAYER met2 ;
      RECT 314.570 0.000 314.710 0.420 ;
    END
  END rw0_rd_out[48]
  PIN rw0_rd_out[49]
    DIRECTION OUTPUT ;
    USE SIGNAL ;
    SHAPE ABUTMENT ;
    PORT
      LAYER met2 ;
      RECT 317.330 0.000 317.470 0.420 ;
    END
  END rw0_rd_out[49]
  PIN rw0_rd_out[50]
    DIRECTION OUTPUT ;
    USE SIGNAL ;
    SHAPE ABUTMENT ;
    PORT
      LAYER met2 ;
      RECT 320.090 0.000 320.230 0.420 ;
    END
  END rw0_rd_out[50]
  PIN rw0_rd_out[51]
    DIRECTION OUTPUT ;
    USE SIGNAL ;
    SHAPE ABUTMENT ;
    PORT
      LAYER met2 ;
      RECT 322.850 0.000 322.990 0.420 ;
    END
  END rw0_rd_out[51]
  PIN rw0_rd_out[52]
    DIRECTION OUTPUT ;
    USE SIGNAL ;
    SHAPE ABUTMENT ;
    PORT
      LAYER met2 ;
      RECT 325.610 0.000 325.750 0.420 ;
    END
  END rw0_rd_out[52]
  PIN rw0_rd_out[53]
    DIRECTION OUTPUT ;
    USE SIGNAL ;
    SHAPE ABUTMENT ;
    PORT
      LAYER met2 ;
      RECT 328.370 0.000 328.510 0.420 ;
    END
  END rw0_rd_out[53]
  PIN rw0_rd_out[54]
    DIRECTION OUTPUT ;
    USE SIGNAL ;
    SHAPE ABUTMENT ;
    PORT
      LAYER met2 ;
      RECT 331.130 0.000 331.270 0.420 ;
    END
  END rw0_rd_out[54]
  PIN rw0_rd_out[55]
    DIRECTION OUTPUT ;
    USE SIGNAL ;
    SHAPE ABUTMENT ;
    PORT
      LAYER met2 ;
      RECT 333.890 0.000 334.030 0.420 ;
    END
  END rw0_rd_out[55]
  PIN rw0_rd_out[56]
    DIRECTION OUTPUT ;
    USE SIGNAL ;
    SHAPE ABUTMENT ;
    PORT
      LAYER met2 ;
      RECT 336.650 0.000 336.790 0.420 ;
    END
  END rw0_rd_out[56]
  PIN rw0_rd_out[57]
    DIRECTION OUTPUT ;
    USE SIGNAL ;
    SHAPE ABUTMENT ;
    PORT
      LAYER met2 ;
      RECT 339.410 0.000 339.550 0.420 ;
    END
  END rw0_rd_out[57]
  PIN rw0_rd_out[58]
    DIRECTION OUTPUT ;
    USE SIGNAL ;
    SHAPE ABUTMENT ;
    PORT
      LAYER met2 ;
      RECT 342.170 0.000 342.310 0.420 ;
    END
  END rw0_rd_out[58]
  PIN rw0_rd_out[59]
    DIRECTION OUTPUT ;
    USE SIGNAL ;
    SHAPE ABUTMENT ;
    PORT
      LAYER met2 ;
      RECT 344.930 0.000 345.070 0.420 ;
    END
  END rw0_rd_out[59]
  PIN rw0_rd_out[60]
    DIRECTION OUTPUT ;
    USE SIGNAL ;
    SHAPE ABUTMENT ;
    PORT
      LAYER met2 ;
      RECT 347.690 0.000 347.830 0.420 ;
    END
  END rw0_rd_out[60]
  PIN rw0_rd_out[61]
    DIRECTION OUTPUT ;
    USE SIGNAL ;
    SHAPE ABUTMENT ;
    PORT
      LAYER met2 ;
      RECT 350.450 0.000 350.590 0.420 ;
    END
  END rw0_rd_out[61]
  PIN rw0_rd_out[62]
    DIRECTION OUTPUT ;
    USE SIGNAL ;
    SHAPE ABUTMENT ;
    PORT
      LAYER met2 ;
      RECT 353.210 0.000 353.350 0.420 ;
    END
  END rw0_rd_out[62]
  PIN rw0_rd_out[63]
    DIRECTION OUTPUT ;
    USE SIGNAL ;
    SHAPE ABUTMENT ;
    PORT
      LAYER met2 ;
      RECT 355.970 0.000 356.110 0.420 ;
    END
  END rw0_rd_out[63]
  PIN rw0_rd_out[64]
    DIRECTION OUTPUT ;
    USE SIGNAL ;
    SHAPE ABUTMENT ;
    PORT
      LAYER met2 ;
      RECT 358.730 0.000 358.870 0.420 ;
    END
  END rw0_rd_out[64]
  PIN rw0_rd_out[65]
    DIRECTION OUTPUT ;
    USE SIGNAL ;
    SHAPE ABUTMENT ;
    PORT
      LAYER met2 ;
      RECT 2.690 948.860 2.830 949.280 ;
    END
  END rw0_rd_out[65]
  PIN rw0_rd_out[66]
    DIRECTION OUTPUT ;
    USE SIGNAL ;
    SHAPE ABUTMENT ;
    PORT
      LAYER met2 ;
      RECT 6.830 948.860 6.970 949.280 ;
    END
  END rw0_rd_out[66]
  PIN rw0_rd_out[67]
    DIRECTION OUTPUT ;
    USE SIGNAL ;
    SHAPE ABUTMENT ;
    PORT
      LAYER met2 ;
      RECT 10.970 948.860 11.110 949.280 ;
    END
  END rw0_rd_out[67]
  PIN rw0_rd_out[68]
    DIRECTION OUTPUT ;
    USE SIGNAL ;
    SHAPE ABUTMENT ;
    PORT
      LAYER met2 ;
      RECT 15.110 948.860 15.250 949.280 ;
    END
  END rw0_rd_out[68]
  PIN rw0_rd_out[69]
    DIRECTION OUTPUT ;
    USE SIGNAL ;
    SHAPE ABUTMENT ;
    PORT
      LAYER met2 ;
      RECT 19.250 948.860 19.390 949.280 ;
    END
  END rw0_rd_out[69]
  PIN rw0_rd_out[70]
    DIRECTION OUTPUT ;
    USE SIGNAL ;
    SHAPE ABUTMENT ;
    PORT
      LAYER met2 ;
      RECT 23.390 948.860 23.530 949.280 ;
    END
  END rw0_rd_out[70]
  PIN rw0_rd_out[71]
    DIRECTION OUTPUT ;
    USE SIGNAL ;
    SHAPE ABUTMENT ;
    PORT
      LAYER met2 ;
      RECT 27.530 948.860 27.670 949.280 ;
    END
  END rw0_rd_out[71]
  PIN rw0_rd_out[72]
    DIRECTION OUTPUT ;
    USE SIGNAL ;
    SHAPE ABUTMENT ;
    PORT
      LAYER met2 ;
      RECT 31.670 948.860 31.810 949.280 ;
    END
  END rw0_rd_out[72]
  PIN rw0_rd_out[73]
    DIRECTION OUTPUT ;
    USE SIGNAL ;
    SHAPE ABUTMENT ;
    PORT
      LAYER met2 ;
      RECT 35.810 948.860 35.950 949.280 ;
    END
  END rw0_rd_out[73]
  PIN rw0_rd_out[74]
    DIRECTION OUTPUT ;
    USE SIGNAL ;
    SHAPE ABUTMENT ;
    PORT
      LAYER met2 ;
      RECT 39.950 948.860 40.090 949.280 ;
    END
  END rw0_rd_out[74]
  PIN rw0_rd_out[75]
    DIRECTION OUTPUT ;
    USE SIGNAL ;
    SHAPE ABUTMENT ;
    PORT
      LAYER met2 ;
      RECT 44.090 948.860 44.230 949.280 ;
    END
  END rw0_rd_out[75]
  PIN rw0_rd_out[76]
    DIRECTION OUTPUT ;
    USE SIGNAL ;
    SHAPE ABUTMENT ;
    PORT
      LAYER met2 ;
      RECT 48.230 948.860 48.370 949.280 ;
    END
  END rw0_rd_out[76]
  PIN rw0_rd_out[77]
    DIRECTION OUTPUT ;
    USE SIGNAL ;
    SHAPE ABUTMENT ;
    PORT
      LAYER met2 ;
      RECT 52.370 948.860 52.510 949.280 ;
    END
  END rw0_rd_out[77]
  PIN rw0_rd_out[78]
    DIRECTION OUTPUT ;
    USE SIGNAL ;
    SHAPE ABUTMENT ;
    PORT
      LAYER met2 ;
      RECT 56.510 948.860 56.650 949.280 ;
    END
  END rw0_rd_out[78]
  PIN rw0_rd_out[79]
    DIRECTION OUTPUT ;
    USE SIGNAL ;
    SHAPE ABUTMENT ;
    PORT
      LAYER met2 ;
      RECT 60.650 948.860 60.790 949.280 ;
    END
  END rw0_rd_out[79]
  PIN rw0_rd_out[80]
    DIRECTION OUTPUT ;
    USE SIGNAL ;
    SHAPE ABUTMENT ;
    PORT
      LAYER met2 ;
      RECT 64.790 948.860 64.930 949.280 ;
    END
  END rw0_rd_out[80]
  PIN rw0_rd_out[81]
    DIRECTION OUTPUT ;
    USE SIGNAL ;
    SHAPE ABUTMENT ;
    PORT
      LAYER met2 ;
      RECT 68.930 948.860 69.070 949.280 ;
    END
  END rw0_rd_out[81]
  PIN rw0_rd_out[82]
    DIRECTION OUTPUT ;
    USE SIGNAL ;
    SHAPE ABUTMENT ;
    PORT
      LAYER met2 ;
      RECT 73.070 948.860 73.210 949.280 ;
    END
  END rw0_rd_out[82]
  PIN rw0_rd_out[83]
    DIRECTION OUTPUT ;
    USE SIGNAL ;
    SHAPE ABUTMENT ;
    PORT
      LAYER met2 ;
      RECT 77.210 948.860 77.350 949.280 ;
    END
  END rw0_rd_out[83]
  PIN rw0_rd_out[84]
    DIRECTION OUTPUT ;
    USE SIGNAL ;
    SHAPE ABUTMENT ;
    PORT
      LAYER met2 ;
      RECT 81.350 948.860 81.490 949.280 ;
    END
  END rw0_rd_out[84]
  PIN rw0_rd_out[85]
    DIRECTION OUTPUT ;
    USE SIGNAL ;
    SHAPE ABUTMENT ;
    PORT
      LAYER met2 ;
      RECT 85.490 948.860 85.630 949.280 ;
    END
  END rw0_rd_out[85]
  PIN rw0_rd_out[86]
    DIRECTION OUTPUT ;
    USE SIGNAL ;
    SHAPE ABUTMENT ;
    PORT
      LAYER met2 ;
      RECT 89.630 948.860 89.770 949.280 ;
    END
  END rw0_rd_out[86]
  PIN rw0_rd_out[87]
    DIRECTION OUTPUT ;
    USE SIGNAL ;
    SHAPE ABUTMENT ;
    PORT
      LAYER met2 ;
      RECT 93.770 948.860 93.910 949.280 ;
    END
  END rw0_rd_out[87]
  PIN rw0_rd_out[88]
    DIRECTION OUTPUT ;
    USE SIGNAL ;
    SHAPE ABUTMENT ;
    PORT
      LAYER met2 ;
      RECT 97.910 948.860 98.050 949.280 ;
    END
  END rw0_rd_out[88]
  PIN rw0_rd_out[89]
    DIRECTION OUTPUT ;
    USE SIGNAL ;
    SHAPE ABUTMENT ;
    PORT
      LAYER met2 ;
      RECT 102.050 948.860 102.190 949.280 ;
    END
  END rw0_rd_out[89]
  PIN rw0_rd_out[90]
    DIRECTION OUTPUT ;
    USE SIGNAL ;
    SHAPE ABUTMENT ;
    PORT
      LAYER met2 ;
      RECT 106.190 948.860 106.330 949.280 ;
    END
  END rw0_rd_out[90]
  PIN rw0_rd_out[91]
    DIRECTION OUTPUT ;
    USE SIGNAL ;
    SHAPE ABUTMENT ;
    PORT
      LAYER met2 ;
      RECT 110.330 948.860 110.470 949.280 ;
    END
  END rw0_rd_out[91]
  PIN rw0_rd_out[92]
    DIRECTION OUTPUT ;
    USE SIGNAL ;
    SHAPE ABUTMENT ;
    PORT
      LAYER met2 ;
      RECT 114.470 948.860 114.610 949.280 ;
    END
  END rw0_rd_out[92]
  PIN rw0_rd_out[93]
    DIRECTION OUTPUT ;
    USE SIGNAL ;
    SHAPE ABUTMENT ;
    PORT
      LAYER met2 ;
      RECT 118.610 948.860 118.750 949.280 ;
    END
  END rw0_rd_out[93]
  PIN rw0_rd_out[94]
    DIRECTION OUTPUT ;
    USE SIGNAL ;
    SHAPE ABUTMENT ;
    PORT
      LAYER met2 ;
      RECT 122.750 948.860 122.890 949.280 ;
    END
  END rw0_rd_out[94]
  PIN rw0_rd_out[95]
    DIRECTION OUTPUT ;
    USE SIGNAL ;
    SHAPE ABUTMENT ;
    PORT
      LAYER met2 ;
      RECT 126.890 948.860 127.030 949.280 ;
    END
  END rw0_rd_out[95]
  PIN rw0_rd_out[96]
    DIRECTION OUTPUT ;
    USE SIGNAL ;
    SHAPE ABUTMENT ;
    PORT
      LAYER met2 ;
      RECT 131.030 948.860 131.170 949.280 ;
    END
  END rw0_rd_out[96]
  PIN rw0_rd_out[97]
    DIRECTION OUTPUT ;
    USE SIGNAL ;
    SHAPE ABUTMENT ;
    PORT
      LAYER met2 ;
      RECT 135.170 948.860 135.310 949.280 ;
    END
  END rw0_rd_out[97]
  PIN rw0_rd_out[98]
    DIRECTION OUTPUT ;
    USE SIGNAL ;
    SHAPE ABUTMENT ;
    PORT
      LAYER met2 ;
      RECT 139.310 948.860 139.450 949.280 ;
    END
  END rw0_rd_out[98]
  PIN rw0_rd_out[99]
    DIRECTION OUTPUT ;
    USE SIGNAL ;
    SHAPE ABUTMENT ;
    PORT
      LAYER met2 ;
      RECT 143.450 948.860 143.590 949.280 ;
    END
  END rw0_rd_out[99]
  PIN rw0_rd_out[100]
    DIRECTION OUTPUT ;
    USE SIGNAL ;
    SHAPE ABUTMENT ;
    PORT
      LAYER met2 ;
      RECT 147.590 948.860 147.730 949.280 ;
    END
  END rw0_rd_out[100]
  PIN rw0_rd_out[101]
    DIRECTION OUTPUT ;
    USE SIGNAL ;
    SHAPE ABUTMENT ;
    PORT
      LAYER met2 ;
      RECT 151.730 948.860 151.870 949.280 ;
    END
  END rw0_rd_out[101]
  PIN rw0_rd_out[102]
    DIRECTION OUTPUT ;
    USE SIGNAL ;
    SHAPE ABUTMENT ;
    PORT
      LAYER met2 ;
      RECT 155.870 948.860 156.010 949.280 ;
    END
  END rw0_rd_out[102]
  PIN rw0_rd_out[103]
    DIRECTION OUTPUT ;
    USE SIGNAL ;
    SHAPE ABUTMENT ;
    PORT
      LAYER met2 ;
      RECT 160.010 948.860 160.150 949.280 ;
    END
  END rw0_rd_out[103]
  PIN rw0_rd_out[104]
    DIRECTION OUTPUT ;
    USE SIGNAL ;
    SHAPE ABUTMENT ;
    PORT
      LAYER met2 ;
      RECT 164.150 948.860 164.290 949.280 ;
    END
  END rw0_rd_out[104]
  PIN rw0_rd_out[105]
    DIRECTION OUTPUT ;
    USE SIGNAL ;
    SHAPE ABUTMENT ;
    PORT
      LAYER met2 ;
      RECT 168.290 948.860 168.430 949.280 ;
    END
  END rw0_rd_out[105]
  PIN rw0_rd_out[106]
    DIRECTION OUTPUT ;
    USE SIGNAL ;
    SHAPE ABUTMENT ;
    PORT
      LAYER met2 ;
      RECT 172.430 948.860 172.570 949.280 ;
    END
  END rw0_rd_out[106]
  PIN rw0_rd_out[107]
    DIRECTION OUTPUT ;
    USE SIGNAL ;
    SHAPE ABUTMENT ;
    PORT
      LAYER met2 ;
      RECT 176.570 948.860 176.710 949.280 ;
    END
  END rw0_rd_out[107]
  PIN rw0_rd_out[108]
    DIRECTION OUTPUT ;
    USE SIGNAL ;
    SHAPE ABUTMENT ;
    PORT
      LAYER met2 ;
      RECT 180.710 948.860 180.850 949.280 ;
    END
  END rw0_rd_out[108]
  PIN rw0_rd_out[109]
    DIRECTION OUTPUT ;
    USE SIGNAL ;
    SHAPE ABUTMENT ;
    PORT
      LAYER met2 ;
      RECT 184.850 948.860 184.990 949.280 ;
    END
  END rw0_rd_out[109]
  PIN rw0_rd_out[110]
    DIRECTION OUTPUT ;
    USE SIGNAL ;
    SHAPE ABUTMENT ;
    PORT
      LAYER met2 ;
      RECT 188.990 948.860 189.130 949.280 ;
    END
  END rw0_rd_out[110]
  PIN rw0_rd_out[111]
    DIRECTION OUTPUT ;
    USE SIGNAL ;
    SHAPE ABUTMENT ;
    PORT
      LAYER met2 ;
      RECT 193.130 948.860 193.270 949.280 ;
    END
  END rw0_rd_out[111]
  PIN rw0_rd_out[112]
    DIRECTION OUTPUT ;
    USE SIGNAL ;
    SHAPE ABUTMENT ;
    PORT
      LAYER met2 ;
      RECT 197.270 948.860 197.410 949.280 ;
    END
  END rw0_rd_out[112]
  PIN rw0_rd_out[113]
    DIRECTION OUTPUT ;
    USE SIGNAL ;
    SHAPE ABUTMENT ;
    PORT
      LAYER met2 ;
      RECT 201.410 948.860 201.550 949.280 ;
    END
  END rw0_rd_out[113]
  PIN rw0_rd_out[114]
    DIRECTION OUTPUT ;
    USE SIGNAL ;
    SHAPE ABUTMENT ;
    PORT
      LAYER met2 ;
      RECT 205.550 948.860 205.690 949.280 ;
    END
  END rw0_rd_out[114]
  PIN rw0_rd_out[115]
    DIRECTION OUTPUT ;
    USE SIGNAL ;
    SHAPE ABUTMENT ;
    PORT
      LAYER met2 ;
      RECT 209.690 948.860 209.830 949.280 ;
    END
  END rw0_rd_out[115]
  PIN rw0_rd_out[116]
    DIRECTION OUTPUT ;
    USE SIGNAL ;
    SHAPE ABUTMENT ;
    PORT
      LAYER met2 ;
      RECT 213.830 948.860 213.970 949.280 ;
    END
  END rw0_rd_out[116]
  PIN rw0_rd_out[117]
    DIRECTION OUTPUT ;
    USE SIGNAL ;
    SHAPE ABUTMENT ;
    PORT
      LAYER met2 ;
      RECT 217.970 948.860 218.110 949.280 ;
    END
  END rw0_rd_out[117]
  PIN rw0_rd_out[118]
    DIRECTION OUTPUT ;
    USE SIGNAL ;
    SHAPE ABUTMENT ;
    PORT
      LAYER met2 ;
      RECT 222.110 948.860 222.250 949.280 ;
    END
  END rw0_rd_out[118]
  PIN rw0_rd_out[119]
    DIRECTION OUTPUT ;
    USE SIGNAL ;
    SHAPE ABUTMENT ;
    PORT
      LAYER met2 ;
      RECT 226.250 948.860 226.390 949.280 ;
    END
  END rw0_rd_out[119]
  PIN rw0_rd_out[120]
    DIRECTION OUTPUT ;
    USE SIGNAL ;
    SHAPE ABUTMENT ;
    PORT
      LAYER met2 ;
      RECT 230.390 948.860 230.530 949.280 ;
    END
  END rw0_rd_out[120]
  PIN rw0_rd_out[121]
    DIRECTION OUTPUT ;
    USE SIGNAL ;
    SHAPE ABUTMENT ;
    PORT
      LAYER met2 ;
      RECT 234.530 948.860 234.670 949.280 ;
    END
  END rw0_rd_out[121]
  PIN rw0_rd_out[122]
    DIRECTION OUTPUT ;
    USE SIGNAL ;
    SHAPE ABUTMENT ;
    PORT
      LAYER met2 ;
      RECT 238.670 948.860 238.810 949.280 ;
    END
  END rw0_rd_out[122]
  PIN rw0_rd_out[123]
    DIRECTION OUTPUT ;
    USE SIGNAL ;
    SHAPE ABUTMENT ;
    PORT
      LAYER met2 ;
      RECT 242.810 948.860 242.950 949.280 ;
    END
  END rw0_rd_out[123]
  PIN rw0_rd_out[124]
    DIRECTION OUTPUT ;
    USE SIGNAL ;
    SHAPE ABUTMENT ;
    PORT
      LAYER met2 ;
      RECT 246.950 948.860 247.090 949.280 ;
    END
  END rw0_rd_out[124]
  PIN rw0_rd_out[125]
    DIRECTION OUTPUT ;
    USE SIGNAL ;
    SHAPE ABUTMENT ;
    PORT
      LAYER met2 ;
      RECT 251.090 948.860 251.230 949.280 ;
    END
  END rw0_rd_out[125]
  PIN rw0_rd_out[126]
    DIRECTION OUTPUT ;
    USE SIGNAL ;
    SHAPE ABUTMENT ;
    PORT
      LAYER met2 ;
      RECT 255.230 948.860 255.370 949.280 ;
    END
  END rw0_rd_out[126]
  PIN rw0_rd_out[127]
    DIRECTION OUTPUT ;
    USE SIGNAL ;
    SHAPE ABUTMENT ;
    PORT
      LAYER met2 ;
      RECT 259.370 948.860 259.510 949.280 ;
    END
  END rw0_rd_out[127]
  PIN rw0_rd_out[128]
    DIRECTION OUTPUT ;
    USE SIGNAL ;
    SHAPE ABUTMENT ;
    PORT
      LAYER met2 ;
      RECT 263.510 948.860 263.650 949.280 ;
    END
  END rw0_rd_out[128]
  PIN rw0_rd_out[129]
    DIRECTION OUTPUT ;
    USE SIGNAL ;
    SHAPE ABUTMENT ;
    PORT
      LAYER met2 ;
      RECT 267.650 948.860 267.790 949.280 ;
    END
  END rw0_rd_out[129]
  PIN r0_rd_out[0]
    DIRECTION OUTPUT ;
    USE SIGNAL ;
    SHAPE ABUTMENT ;
    PORT
      LAYER met2 ;
      RECT 361.490 0.000 361.630 0.420 ;
    END
  END r0_rd_out[0]
  PIN r0_rd_out[1]
    DIRECTION OUTPUT ;
    USE SIGNAL ;
    SHAPE ABUTMENT ;
    PORT
      LAYER met2 ;
      RECT 364.250 0.000 364.390 0.420 ;
    END
  END r0_rd_out[1]
  PIN r0_rd_out[2]
    DIRECTION OUTPUT ;
    USE SIGNAL ;
    SHAPE ABUTMENT ;
    PORT
      LAYER met2 ;
      RECT 367.010 0.000 367.150 0.420 ;
    END
  END r0_rd_out[2]
  PIN r0_rd_out[3]
    DIRECTION OUTPUT ;
    USE SIGNAL ;
    SHAPE ABUTMENT ;
    PORT
      LAYER met2 ;
      RECT 369.770 0.000 369.910 0.420 ;
    END
  END r0_rd_out[3]
  PIN r0_rd_out[4]
    DIRECTION OUTPUT ;
    USE SIGNAL ;
    SHAPE ABUTMENT ;
    PORT
      LAYER met2 ;
      RECT 372.530 0.000 372.670 0.420 ;
    END
  END r0_rd_out[4]
  PIN r0_rd_out[5]
    DIRECTION OUTPUT ;
    USE SIGNAL ;
    SHAPE ABUTMENT ;
    PORT
      LAYER met2 ;
      RECT 375.290 0.000 375.430 0.420 ;
    END
  END r0_rd_out[5]
  PIN r0_rd_out[6]
    DIRECTION OUTPUT ;
    USE SIGNAL ;
    SHAPE ABUTMENT ;
    PORT
      LAYER met2 ;
      RECT 378.050 0.000 378.190 0.420 ;
    END
  END r0_rd_out[6]
  PIN r0_rd_out[7]
    DIRECTION OUTPUT ;
    USE SIGNAL ;
    SHAPE ABUTMENT ;
    PORT
      LAYER met2 ;
      RECT 380.810 0.000 380.950 0.420 ;
    END
  END r0_rd_out[7]
  PIN r0_rd_out[8]
    DIRECTION OUTPUT ;
    USE SIGNAL ;
    SHAPE ABUTMENT ;
    PORT
      LAYER met2 ;
      RECT 383.570 0.000 383.710 0.420 ;
    END
  END r0_rd_out[8]
  PIN r0_rd_out[9]
    DIRECTION OUTPUT ;
    USE SIGNAL ;
    SHAPE ABUTMENT ;
    PORT
      LAYER met2 ;
      RECT 386.330 0.000 386.470 0.420 ;
    END
  END r0_rd_out[9]
  PIN r0_rd_out[10]
    DIRECTION OUTPUT ;
    USE SIGNAL ;
    SHAPE ABUTMENT ;
    PORT
      LAYER met2 ;
      RECT 389.090 0.000 389.230 0.420 ;
    END
  END r0_rd_out[10]
  PIN r0_rd_out[11]
    DIRECTION OUTPUT ;
    USE SIGNAL ;
    SHAPE ABUTMENT ;
    PORT
      LAYER met2 ;
      RECT 391.850 0.000 391.990 0.420 ;
    END
  END r0_rd_out[11]
  PIN r0_rd_out[12]
    DIRECTION OUTPUT ;
    USE SIGNAL ;
    SHAPE ABUTMENT ;
    PORT
      LAYER met2 ;
      RECT 394.610 0.000 394.750 0.420 ;
    END
  END r0_rd_out[12]
  PIN r0_rd_out[13]
    DIRECTION OUTPUT ;
    USE SIGNAL ;
    SHAPE ABUTMENT ;
    PORT
      LAYER met2 ;
      RECT 397.370 0.000 397.510 0.420 ;
    END
  END r0_rd_out[13]
  PIN r0_rd_out[14]
    DIRECTION OUTPUT ;
    USE SIGNAL ;
    SHAPE ABUTMENT ;
    PORT
      LAYER met2 ;
      RECT 400.130 0.000 400.270 0.420 ;
    END
  END r0_rd_out[14]
  PIN r0_rd_out[15]
    DIRECTION OUTPUT ;
    USE SIGNAL ;
    SHAPE ABUTMENT ;
    PORT
      LAYER met2 ;
      RECT 402.890 0.000 403.030 0.420 ;
    END
  END r0_rd_out[15]
  PIN r0_rd_out[16]
    DIRECTION OUTPUT ;
    USE SIGNAL ;
    SHAPE ABUTMENT ;
    PORT
      LAYER met2 ;
      RECT 405.650 0.000 405.790 0.420 ;
    END
  END r0_rd_out[16]
  PIN r0_rd_out[17]
    DIRECTION OUTPUT ;
    USE SIGNAL ;
    SHAPE ABUTMENT ;
    PORT
      LAYER met2 ;
      RECT 408.410 0.000 408.550 0.420 ;
    END
  END r0_rd_out[17]
  PIN r0_rd_out[18]
    DIRECTION OUTPUT ;
    USE SIGNAL ;
    SHAPE ABUTMENT ;
    PORT
      LAYER met2 ;
      RECT 411.170 0.000 411.310 0.420 ;
    END
  END r0_rd_out[18]
  PIN r0_rd_out[19]
    DIRECTION OUTPUT ;
    USE SIGNAL ;
    SHAPE ABUTMENT ;
    PORT
      LAYER met2 ;
      RECT 413.930 0.000 414.070 0.420 ;
    END
  END r0_rd_out[19]
  PIN r0_rd_out[20]
    DIRECTION OUTPUT ;
    USE SIGNAL ;
    SHAPE ABUTMENT ;
    PORT
      LAYER met2 ;
      RECT 416.690 0.000 416.830 0.420 ;
    END
  END r0_rd_out[20]
  PIN r0_rd_out[21]
    DIRECTION OUTPUT ;
    USE SIGNAL ;
    SHAPE ABUTMENT ;
    PORT
      LAYER met2 ;
      RECT 419.450 0.000 419.590 0.420 ;
    END
  END r0_rd_out[21]
  PIN r0_rd_out[22]
    DIRECTION OUTPUT ;
    USE SIGNAL ;
    SHAPE ABUTMENT ;
    PORT
      LAYER met2 ;
      RECT 422.210 0.000 422.350 0.420 ;
    END
  END r0_rd_out[22]
  PIN r0_rd_out[23]
    DIRECTION OUTPUT ;
    USE SIGNAL ;
    SHAPE ABUTMENT ;
    PORT
      LAYER met2 ;
      RECT 424.970 0.000 425.110 0.420 ;
    END
  END r0_rd_out[23]
  PIN r0_rd_out[24]
    DIRECTION OUTPUT ;
    USE SIGNAL ;
    SHAPE ABUTMENT ;
    PORT
      LAYER met2 ;
      RECT 427.730 0.000 427.870 0.420 ;
    END
  END r0_rd_out[24]
  PIN r0_rd_out[25]
    DIRECTION OUTPUT ;
    USE SIGNAL ;
    SHAPE ABUTMENT ;
    PORT
      LAYER met2 ;
      RECT 430.490 0.000 430.630 0.420 ;
    END
  END r0_rd_out[25]
  PIN r0_rd_out[26]
    DIRECTION OUTPUT ;
    USE SIGNAL ;
    SHAPE ABUTMENT ;
    PORT
      LAYER met2 ;
      RECT 433.250 0.000 433.390 0.420 ;
    END
  END r0_rd_out[26]
  PIN r0_rd_out[27]
    DIRECTION OUTPUT ;
    USE SIGNAL ;
    SHAPE ABUTMENT ;
    PORT
      LAYER met2 ;
      RECT 436.010 0.000 436.150 0.420 ;
    END
  END r0_rd_out[27]
  PIN r0_rd_out[28]
    DIRECTION OUTPUT ;
    USE SIGNAL ;
    SHAPE ABUTMENT ;
    PORT
      LAYER met2 ;
      RECT 438.770 0.000 438.910 0.420 ;
    END
  END r0_rd_out[28]
  PIN r0_rd_out[29]
    DIRECTION OUTPUT ;
    USE SIGNAL ;
    SHAPE ABUTMENT ;
    PORT
      LAYER met2 ;
      RECT 441.530 0.000 441.670 0.420 ;
    END
  END r0_rd_out[29]
  PIN r0_rd_out[30]
    DIRECTION OUTPUT ;
    USE SIGNAL ;
    SHAPE ABUTMENT ;
    PORT
      LAYER met2 ;
      RECT 444.290 0.000 444.430 0.420 ;
    END
  END r0_rd_out[30]
  PIN r0_rd_out[31]
    DIRECTION OUTPUT ;
    USE SIGNAL ;
    SHAPE ABUTMENT ;
    PORT
      LAYER met2 ;
      RECT 447.050 0.000 447.190 0.420 ;
    END
  END r0_rd_out[31]
  PIN r0_rd_out[32]
    DIRECTION OUTPUT ;
    USE SIGNAL ;
    SHAPE ABUTMENT ;
    PORT
      LAYER met2 ;
      RECT 449.810 0.000 449.950 0.420 ;
    END
  END r0_rd_out[32]
  PIN r0_rd_out[33]
    DIRECTION OUTPUT ;
    USE SIGNAL ;
    SHAPE ABUTMENT ;
    PORT
      LAYER met2 ;
      RECT 452.570 0.000 452.710 0.420 ;
    END
  END r0_rd_out[33]
  PIN r0_rd_out[34]
    DIRECTION OUTPUT ;
    USE SIGNAL ;
    SHAPE ABUTMENT ;
    PORT
      LAYER met2 ;
      RECT 455.330 0.000 455.470 0.420 ;
    END
  END r0_rd_out[34]
  PIN r0_rd_out[35]
    DIRECTION OUTPUT ;
    USE SIGNAL ;
    SHAPE ABUTMENT ;
    PORT
      LAYER met2 ;
      RECT 458.090 0.000 458.230 0.420 ;
    END
  END r0_rd_out[35]
  PIN r0_rd_out[36]
    DIRECTION OUTPUT ;
    USE SIGNAL ;
    SHAPE ABUTMENT ;
    PORT
      LAYER met2 ;
      RECT 460.850 0.000 460.990 0.420 ;
    END
  END r0_rd_out[36]
  PIN r0_rd_out[37]
    DIRECTION OUTPUT ;
    USE SIGNAL ;
    SHAPE ABUTMENT ;
    PORT
      LAYER met2 ;
      RECT 463.610 0.000 463.750 0.420 ;
    END
  END r0_rd_out[37]
  PIN r0_rd_out[38]
    DIRECTION OUTPUT ;
    USE SIGNAL ;
    SHAPE ABUTMENT ;
    PORT
      LAYER met2 ;
      RECT 466.370 0.000 466.510 0.420 ;
    END
  END r0_rd_out[38]
  PIN r0_rd_out[39]
    DIRECTION OUTPUT ;
    USE SIGNAL ;
    SHAPE ABUTMENT ;
    PORT
      LAYER met2 ;
      RECT 469.130 0.000 469.270 0.420 ;
    END
  END r0_rd_out[39]
  PIN r0_rd_out[40]
    DIRECTION OUTPUT ;
    USE SIGNAL ;
    SHAPE ABUTMENT ;
    PORT
      LAYER met2 ;
      RECT 471.890 0.000 472.030 0.420 ;
    END
  END r0_rd_out[40]
  PIN r0_rd_out[41]
    DIRECTION OUTPUT ;
    USE SIGNAL ;
    SHAPE ABUTMENT ;
    PORT
      LAYER met2 ;
      RECT 474.650 0.000 474.790 0.420 ;
    END
  END r0_rd_out[41]
  PIN r0_rd_out[42]
    DIRECTION OUTPUT ;
    USE SIGNAL ;
    SHAPE ABUTMENT ;
    PORT
      LAYER met2 ;
      RECT 477.410 0.000 477.550 0.420 ;
    END
  END r0_rd_out[42]
  PIN r0_rd_out[43]
    DIRECTION OUTPUT ;
    USE SIGNAL ;
    SHAPE ABUTMENT ;
    PORT
      LAYER met2 ;
      RECT 480.170 0.000 480.310 0.420 ;
    END
  END r0_rd_out[43]
  PIN r0_rd_out[44]
    DIRECTION OUTPUT ;
    USE SIGNAL ;
    SHAPE ABUTMENT ;
    PORT
      LAYER met2 ;
      RECT 482.930 0.000 483.070 0.420 ;
    END
  END r0_rd_out[44]
  PIN r0_rd_out[45]
    DIRECTION OUTPUT ;
    USE SIGNAL ;
    SHAPE ABUTMENT ;
    PORT
      LAYER met2 ;
      RECT 485.690 0.000 485.830 0.420 ;
    END
  END r0_rd_out[45]
  PIN r0_rd_out[46]
    DIRECTION OUTPUT ;
    USE SIGNAL ;
    SHAPE ABUTMENT ;
    PORT
      LAYER met2 ;
      RECT 488.450 0.000 488.590 0.420 ;
    END
  END r0_rd_out[46]
  PIN r0_rd_out[47]
    DIRECTION OUTPUT ;
    USE SIGNAL ;
    SHAPE ABUTMENT ;
    PORT
      LAYER met2 ;
      RECT 491.210 0.000 491.350 0.420 ;
    END
  END r0_rd_out[47]
  PIN r0_rd_out[48]
    DIRECTION OUTPUT ;
    USE SIGNAL ;
    SHAPE ABUTMENT ;
    PORT
      LAYER met2 ;
      RECT 493.970 0.000 494.110 0.420 ;
    END
  END r0_rd_out[48]
  PIN r0_rd_out[49]
    DIRECTION OUTPUT ;
    USE SIGNAL ;
    SHAPE ABUTMENT ;
    PORT
      LAYER met2 ;
      RECT 496.730 0.000 496.870 0.420 ;
    END
  END r0_rd_out[49]
  PIN r0_rd_out[50]
    DIRECTION OUTPUT ;
    USE SIGNAL ;
    SHAPE ABUTMENT ;
    PORT
      LAYER met2 ;
      RECT 499.490 0.000 499.630 0.420 ;
    END
  END r0_rd_out[50]
  PIN r0_rd_out[51]
    DIRECTION OUTPUT ;
    USE SIGNAL ;
    SHAPE ABUTMENT ;
    PORT
      LAYER met2 ;
      RECT 502.250 0.000 502.390 0.420 ;
    END
  END r0_rd_out[51]
  PIN r0_rd_out[52]
    DIRECTION OUTPUT ;
    USE SIGNAL ;
    SHAPE ABUTMENT ;
    PORT
      LAYER met2 ;
      RECT 505.010 0.000 505.150 0.420 ;
    END
  END r0_rd_out[52]
  PIN r0_rd_out[53]
    DIRECTION OUTPUT ;
    USE SIGNAL ;
    SHAPE ABUTMENT ;
    PORT
      LAYER met2 ;
      RECT 507.770 0.000 507.910 0.420 ;
    END
  END r0_rd_out[53]
  PIN r0_rd_out[54]
    DIRECTION OUTPUT ;
    USE SIGNAL ;
    SHAPE ABUTMENT ;
    PORT
      LAYER met2 ;
      RECT 510.530 0.000 510.670 0.420 ;
    END
  END r0_rd_out[54]
  PIN r0_rd_out[55]
    DIRECTION OUTPUT ;
    USE SIGNAL ;
    SHAPE ABUTMENT ;
    PORT
      LAYER met2 ;
      RECT 513.290 0.000 513.430 0.420 ;
    END
  END r0_rd_out[55]
  PIN r0_rd_out[56]
    DIRECTION OUTPUT ;
    USE SIGNAL ;
    SHAPE ABUTMENT ;
    PORT
      LAYER met2 ;
      RECT 516.050 0.000 516.190 0.420 ;
    END
  END r0_rd_out[56]
  PIN r0_rd_out[57]
    DIRECTION OUTPUT ;
    USE SIGNAL ;
    SHAPE ABUTMENT ;
    PORT
      LAYER met2 ;
      RECT 518.810 0.000 518.950 0.420 ;
    END
  END r0_rd_out[57]
  PIN r0_rd_out[58]
    DIRECTION OUTPUT ;
    USE SIGNAL ;
    SHAPE ABUTMENT ;
    PORT
      LAYER met2 ;
      RECT 521.570 0.000 521.710 0.420 ;
    END
  END r0_rd_out[58]
  PIN r0_rd_out[59]
    DIRECTION OUTPUT ;
    USE SIGNAL ;
    SHAPE ABUTMENT ;
    PORT
      LAYER met2 ;
      RECT 524.330 0.000 524.470 0.420 ;
    END
  END r0_rd_out[59]
  PIN r0_rd_out[60]
    DIRECTION OUTPUT ;
    USE SIGNAL ;
    SHAPE ABUTMENT ;
    PORT
      LAYER met2 ;
      RECT 527.090 0.000 527.230 0.420 ;
    END
  END r0_rd_out[60]
  PIN r0_rd_out[61]
    DIRECTION OUTPUT ;
    USE SIGNAL ;
    SHAPE ABUTMENT ;
    PORT
      LAYER met2 ;
      RECT 529.850 0.000 529.990 0.420 ;
    END
  END r0_rd_out[61]
  PIN r0_rd_out[62]
    DIRECTION OUTPUT ;
    USE SIGNAL ;
    SHAPE ABUTMENT ;
    PORT
      LAYER met2 ;
      RECT 532.610 0.000 532.750 0.420 ;
    END
  END r0_rd_out[62]
  PIN r0_rd_out[63]
    DIRECTION OUTPUT ;
    USE SIGNAL ;
    SHAPE ABUTMENT ;
    PORT
      LAYER met2 ;
      RECT 535.370 0.000 535.510 0.420 ;
    END
  END r0_rd_out[63]
  PIN r0_rd_out[64]
    DIRECTION OUTPUT ;
    USE SIGNAL ;
    SHAPE ABUTMENT ;
    PORT
      LAYER met2 ;
      RECT 538.130 0.000 538.270 0.420 ;
    END
  END r0_rd_out[64]
  PIN r0_rd_out[65]
    DIRECTION OUTPUT ;
    USE SIGNAL ;
    SHAPE ABUTMENT ;
    PORT
      LAYER met2 ;
      RECT 271.790 948.860 271.930 949.280 ;
    END
  END r0_rd_out[65]
  PIN r0_rd_out[66]
    DIRECTION OUTPUT ;
    USE SIGNAL ;
    SHAPE ABUTMENT ;
    PORT
      LAYER met2 ;
      RECT 275.930 948.860 276.070 949.280 ;
    END
  END r0_rd_out[66]
  PIN r0_rd_out[67]
    DIRECTION OUTPUT ;
    USE SIGNAL ;
    SHAPE ABUTMENT ;
    PORT
      LAYER met2 ;
      RECT 280.070 948.860 280.210 949.280 ;
    END
  END r0_rd_out[67]
  PIN r0_rd_out[68]
    DIRECTION OUTPUT ;
    USE SIGNAL ;
    SHAPE ABUTMENT ;
    PORT
      LAYER met2 ;
      RECT 284.210 948.860 284.350 949.280 ;
    END
  END r0_rd_out[68]
  PIN r0_rd_out[69]
    DIRECTION OUTPUT ;
    USE SIGNAL ;
    SHAPE ABUTMENT ;
    PORT
      LAYER met2 ;
      RECT 288.350 948.860 288.490 949.280 ;
    END
  END r0_rd_out[69]
  PIN r0_rd_out[70]
    DIRECTION OUTPUT ;
    USE SIGNAL ;
    SHAPE ABUTMENT ;
    PORT
      LAYER met2 ;
      RECT 292.490 948.860 292.630 949.280 ;
    END
  END r0_rd_out[70]
  PIN r0_rd_out[71]
    DIRECTION OUTPUT ;
    USE SIGNAL ;
    SHAPE ABUTMENT ;
    PORT
      LAYER met2 ;
      RECT 296.630 948.860 296.770 949.280 ;
    END
  END r0_rd_out[71]
  PIN r0_rd_out[72]
    DIRECTION OUTPUT ;
    USE SIGNAL ;
    SHAPE ABUTMENT ;
    PORT
      LAYER met2 ;
      RECT 300.770 948.860 300.910 949.280 ;
    END
  END r0_rd_out[72]
  PIN r0_rd_out[73]
    DIRECTION OUTPUT ;
    USE SIGNAL ;
    SHAPE ABUTMENT ;
    PORT
      LAYER met2 ;
      RECT 304.910 948.860 305.050 949.280 ;
    END
  END r0_rd_out[73]
  PIN r0_rd_out[74]
    DIRECTION OUTPUT ;
    USE SIGNAL ;
    SHAPE ABUTMENT ;
    PORT
      LAYER met2 ;
      RECT 309.050 948.860 309.190 949.280 ;
    END
  END r0_rd_out[74]
  PIN r0_rd_out[75]
    DIRECTION OUTPUT ;
    USE SIGNAL ;
    SHAPE ABUTMENT ;
    PORT
      LAYER met2 ;
      RECT 313.190 948.860 313.330 949.280 ;
    END
  END r0_rd_out[75]
  PIN r0_rd_out[76]
    DIRECTION OUTPUT ;
    USE SIGNAL ;
    SHAPE ABUTMENT ;
    PORT
      LAYER met2 ;
      RECT 317.330 948.860 317.470 949.280 ;
    END
  END r0_rd_out[76]
  PIN r0_rd_out[77]
    DIRECTION OUTPUT ;
    USE SIGNAL ;
    SHAPE ABUTMENT ;
    PORT
      LAYER met2 ;
      RECT 321.470 948.860 321.610 949.280 ;
    END
  END r0_rd_out[77]
  PIN r0_rd_out[78]
    DIRECTION OUTPUT ;
    USE SIGNAL ;
    SHAPE ABUTMENT ;
    PORT
      LAYER met2 ;
      RECT 325.610 948.860 325.750 949.280 ;
    END
  END r0_rd_out[78]
  PIN r0_rd_out[79]
    DIRECTION OUTPUT ;
    USE SIGNAL ;
    SHAPE ABUTMENT ;
    PORT
      LAYER met2 ;
      RECT 329.750 948.860 329.890 949.280 ;
    END
  END r0_rd_out[79]
  PIN r0_rd_out[80]
    DIRECTION OUTPUT ;
    USE SIGNAL ;
    SHAPE ABUTMENT ;
    PORT
      LAYER met2 ;
      RECT 333.890 948.860 334.030 949.280 ;
    END
  END r0_rd_out[80]
  PIN r0_rd_out[81]
    DIRECTION OUTPUT ;
    USE SIGNAL ;
    SHAPE ABUTMENT ;
    PORT
      LAYER met2 ;
      RECT 338.030 948.860 338.170 949.280 ;
    END
  END r0_rd_out[81]
  PIN r0_rd_out[82]
    DIRECTION OUTPUT ;
    USE SIGNAL ;
    SHAPE ABUTMENT ;
    PORT
      LAYER met2 ;
      RECT 342.170 948.860 342.310 949.280 ;
    END
  END r0_rd_out[82]
  PIN r0_rd_out[83]
    DIRECTION OUTPUT ;
    USE SIGNAL ;
    SHAPE ABUTMENT ;
    PORT
      LAYER met2 ;
      RECT 346.310 948.860 346.450 949.280 ;
    END
  END r0_rd_out[83]
  PIN r0_rd_out[84]
    DIRECTION OUTPUT ;
    USE SIGNAL ;
    SHAPE ABUTMENT ;
    PORT
      LAYER met2 ;
      RECT 350.450 948.860 350.590 949.280 ;
    END
  END r0_rd_out[84]
  PIN r0_rd_out[85]
    DIRECTION OUTPUT ;
    USE SIGNAL ;
    SHAPE ABUTMENT ;
    PORT
      LAYER met2 ;
      RECT 354.590 948.860 354.730 949.280 ;
    END
  END r0_rd_out[85]
  PIN r0_rd_out[86]
    DIRECTION OUTPUT ;
    USE SIGNAL ;
    SHAPE ABUTMENT ;
    PORT
      LAYER met2 ;
      RECT 358.730 948.860 358.870 949.280 ;
    END
  END r0_rd_out[86]
  PIN r0_rd_out[87]
    DIRECTION OUTPUT ;
    USE SIGNAL ;
    SHAPE ABUTMENT ;
    PORT
      LAYER met2 ;
      RECT 362.870 948.860 363.010 949.280 ;
    END
  END r0_rd_out[87]
  PIN r0_rd_out[88]
    DIRECTION OUTPUT ;
    USE SIGNAL ;
    SHAPE ABUTMENT ;
    PORT
      LAYER met2 ;
      RECT 367.010 948.860 367.150 949.280 ;
    END
  END r0_rd_out[88]
  PIN r0_rd_out[89]
    DIRECTION OUTPUT ;
    USE SIGNAL ;
    SHAPE ABUTMENT ;
    PORT
      LAYER met2 ;
      RECT 371.150 948.860 371.290 949.280 ;
    END
  END r0_rd_out[89]
  PIN r0_rd_out[90]
    DIRECTION OUTPUT ;
    USE SIGNAL ;
    SHAPE ABUTMENT ;
    PORT
      LAYER met2 ;
      RECT 375.290 948.860 375.430 949.280 ;
    END
  END r0_rd_out[90]
  PIN r0_rd_out[91]
    DIRECTION OUTPUT ;
    USE SIGNAL ;
    SHAPE ABUTMENT ;
    PORT
      LAYER met2 ;
      RECT 379.430 948.860 379.570 949.280 ;
    END
  END r0_rd_out[91]
  PIN r0_rd_out[92]
    DIRECTION OUTPUT ;
    USE SIGNAL ;
    SHAPE ABUTMENT ;
    PORT
      LAYER met2 ;
      RECT 383.570 948.860 383.710 949.280 ;
    END
  END r0_rd_out[92]
  PIN r0_rd_out[93]
    DIRECTION OUTPUT ;
    USE SIGNAL ;
    SHAPE ABUTMENT ;
    PORT
      LAYER met2 ;
      RECT 387.710 948.860 387.850 949.280 ;
    END
  END r0_rd_out[93]
  PIN r0_rd_out[94]
    DIRECTION OUTPUT ;
    USE SIGNAL ;
    SHAPE ABUTMENT ;
    PORT
      LAYER met2 ;
      RECT 391.850 948.860 391.990 949.280 ;
    END
  END r0_rd_out[94]
  PIN r0_rd_out[95]
    DIRECTION OUTPUT ;
    USE SIGNAL ;
    SHAPE ABUTMENT ;
    PORT
      LAYER met2 ;
      RECT 395.990 948.860 396.130 949.280 ;
    END
  END r0_rd_out[95]
  PIN r0_rd_out[96]
    DIRECTION OUTPUT ;
    USE SIGNAL ;
    SHAPE ABUTMENT ;
    PORT
      LAYER met2 ;
      RECT 400.130 948.860 400.270 949.280 ;
    END
  END r0_rd_out[96]
  PIN r0_rd_out[97]
    DIRECTION OUTPUT ;
    USE SIGNAL ;
    SHAPE ABUTMENT ;
    PORT
      LAYER met2 ;
      RECT 404.270 948.860 404.410 949.280 ;
    END
  END r0_rd_out[97]
  PIN r0_rd_out[98]
    DIRECTION OUTPUT ;
    USE SIGNAL ;
    SHAPE ABUTMENT ;
    PORT
      LAYER met2 ;
      RECT 408.410 948.860 408.550 949.280 ;
    END
  END r0_rd_out[98]
  PIN r0_rd_out[99]
    DIRECTION OUTPUT ;
    USE SIGNAL ;
    SHAPE ABUTMENT ;
    PORT
      LAYER met2 ;
      RECT 412.550 948.860 412.690 949.280 ;
    END
  END r0_rd_out[99]
  PIN r0_rd_out[100]
    DIRECTION OUTPUT ;
    USE SIGNAL ;
    SHAPE ABUTMENT ;
    PORT
      LAYER met2 ;
      RECT 416.690 948.860 416.830 949.280 ;
    END
  END r0_rd_out[100]
  PIN r0_rd_out[101]
    DIRECTION OUTPUT ;
    USE SIGNAL ;
    SHAPE ABUTMENT ;
    PORT
      LAYER met2 ;
      RECT 420.830 948.860 420.970 949.280 ;
    END
  END r0_rd_out[101]
  PIN r0_rd_out[102]
    DIRECTION OUTPUT ;
    USE SIGNAL ;
    SHAPE ABUTMENT ;
    PORT
      LAYER met2 ;
      RECT 424.970 948.860 425.110 949.280 ;
    END
  END r0_rd_out[102]
  PIN r0_rd_out[103]
    DIRECTION OUTPUT ;
    USE SIGNAL ;
    SHAPE ABUTMENT ;
    PORT
      LAYER met2 ;
      RECT 429.110 948.860 429.250 949.280 ;
    END
  END r0_rd_out[103]
  PIN r0_rd_out[104]
    DIRECTION OUTPUT ;
    USE SIGNAL ;
    SHAPE ABUTMENT ;
    PORT
      LAYER met2 ;
      RECT 433.250 948.860 433.390 949.280 ;
    END
  END r0_rd_out[104]
  PIN r0_rd_out[105]
    DIRECTION OUTPUT ;
    USE SIGNAL ;
    SHAPE ABUTMENT ;
    PORT
      LAYER met2 ;
      RECT 437.390 948.860 437.530 949.280 ;
    END
  END r0_rd_out[105]
  PIN r0_rd_out[106]
    DIRECTION OUTPUT ;
    USE SIGNAL ;
    SHAPE ABUTMENT ;
    PORT
      LAYER met2 ;
      RECT 441.530 948.860 441.670 949.280 ;
    END
  END r0_rd_out[106]
  PIN r0_rd_out[107]
    DIRECTION OUTPUT ;
    USE SIGNAL ;
    SHAPE ABUTMENT ;
    PORT
      LAYER met2 ;
      RECT 445.670 948.860 445.810 949.280 ;
    END
  END r0_rd_out[107]
  PIN r0_rd_out[108]
    DIRECTION OUTPUT ;
    USE SIGNAL ;
    SHAPE ABUTMENT ;
    PORT
      LAYER met2 ;
      RECT 449.810 948.860 449.950 949.280 ;
    END
  END r0_rd_out[108]
  PIN r0_rd_out[109]
    DIRECTION OUTPUT ;
    USE SIGNAL ;
    SHAPE ABUTMENT ;
    PORT
      LAYER met2 ;
      RECT 453.950 948.860 454.090 949.280 ;
    END
  END r0_rd_out[109]
  PIN r0_rd_out[110]
    DIRECTION OUTPUT ;
    USE SIGNAL ;
    SHAPE ABUTMENT ;
    PORT
      LAYER met2 ;
      RECT 458.090 948.860 458.230 949.280 ;
    END
  END r0_rd_out[110]
  PIN r0_rd_out[111]
    DIRECTION OUTPUT ;
    USE SIGNAL ;
    SHAPE ABUTMENT ;
    PORT
      LAYER met2 ;
      RECT 462.230 948.860 462.370 949.280 ;
    END
  END r0_rd_out[111]
  PIN r0_rd_out[112]
    DIRECTION OUTPUT ;
    USE SIGNAL ;
    SHAPE ABUTMENT ;
    PORT
      LAYER met2 ;
      RECT 466.370 948.860 466.510 949.280 ;
    END
  END r0_rd_out[112]
  PIN r0_rd_out[113]
    DIRECTION OUTPUT ;
    USE SIGNAL ;
    SHAPE ABUTMENT ;
    PORT
      LAYER met2 ;
      RECT 470.510 948.860 470.650 949.280 ;
    END
  END r0_rd_out[113]
  PIN r0_rd_out[114]
    DIRECTION OUTPUT ;
    USE SIGNAL ;
    SHAPE ABUTMENT ;
    PORT
      LAYER met2 ;
      RECT 474.650 948.860 474.790 949.280 ;
    END
  END r0_rd_out[114]
  PIN r0_rd_out[115]
    DIRECTION OUTPUT ;
    USE SIGNAL ;
    SHAPE ABUTMENT ;
    PORT
      LAYER met2 ;
      RECT 478.790 948.860 478.930 949.280 ;
    END
  END r0_rd_out[115]
  PIN r0_rd_out[116]
    DIRECTION OUTPUT ;
    USE SIGNAL ;
    SHAPE ABUTMENT ;
    PORT
      LAYER met2 ;
      RECT 482.930 948.860 483.070 949.280 ;
    END
  END r0_rd_out[116]
  PIN r0_rd_out[117]
    DIRECTION OUTPUT ;
    USE SIGNAL ;
    SHAPE ABUTMENT ;
    PORT
      LAYER met2 ;
      RECT 487.070 948.860 487.210 949.280 ;
    END
  END r0_rd_out[117]
  PIN r0_rd_out[118]
    DIRECTION OUTPUT ;
    USE SIGNAL ;
    SHAPE ABUTMENT ;
    PORT
      LAYER met2 ;
      RECT 491.210 948.860 491.350 949.280 ;
    END
  END r0_rd_out[118]
  PIN r0_rd_out[119]
    DIRECTION OUTPUT ;
    USE SIGNAL ;
    SHAPE ABUTMENT ;
    PORT
      LAYER met2 ;
      RECT 495.350 948.860 495.490 949.280 ;
    END
  END r0_rd_out[119]
  PIN r0_rd_out[120]
    DIRECTION OUTPUT ;
    USE SIGNAL ;
    SHAPE ABUTMENT ;
    PORT
      LAYER met2 ;
      RECT 499.490 948.860 499.630 949.280 ;
    END
  END r0_rd_out[120]
  PIN r0_rd_out[121]
    DIRECTION OUTPUT ;
    USE SIGNAL ;
    SHAPE ABUTMENT ;
    PORT
      LAYER met2 ;
      RECT 503.630 948.860 503.770 949.280 ;
    END
  END r0_rd_out[121]
  PIN r0_rd_out[122]
    DIRECTION OUTPUT ;
    USE SIGNAL ;
    SHAPE ABUTMENT ;
    PORT
      LAYER met2 ;
      RECT 507.770 948.860 507.910 949.280 ;
    END
  END r0_rd_out[122]
  PIN r0_rd_out[123]
    DIRECTION OUTPUT ;
    USE SIGNAL ;
    SHAPE ABUTMENT ;
    PORT
      LAYER met2 ;
      RECT 511.910 948.860 512.050 949.280 ;
    END
  END r0_rd_out[123]
  PIN r0_rd_out[124]
    DIRECTION OUTPUT ;
    USE SIGNAL ;
    SHAPE ABUTMENT ;
    PORT
      LAYER met2 ;
      RECT 516.050 948.860 516.190 949.280 ;
    END
  END r0_rd_out[124]
  PIN r0_rd_out[125]
    DIRECTION OUTPUT ;
    USE SIGNAL ;
    SHAPE ABUTMENT ;
    PORT
      LAYER met2 ;
      RECT 520.190 948.860 520.330 949.280 ;
    END
  END r0_rd_out[125]
  PIN r0_rd_out[126]
    DIRECTION OUTPUT ;
    USE SIGNAL ;
    SHAPE ABUTMENT ;
    PORT
      LAYER met2 ;
      RECT 524.330 948.860 524.470 949.280 ;
    END
  END r0_rd_out[126]
  PIN r0_rd_out[127]
    DIRECTION OUTPUT ;
    USE SIGNAL ;
    SHAPE ABUTMENT ;
    PORT
      LAYER met2 ;
      RECT 528.470 948.860 528.610 949.280 ;
    END
  END r0_rd_out[127]
  PIN r0_rd_out[128]
    DIRECTION OUTPUT ;
    USE SIGNAL ;
    SHAPE ABUTMENT ;
    PORT
      LAYER met2 ;
      RECT 532.610 948.860 532.750 949.280 ;
    END
  END r0_rd_out[128]
  PIN r0_rd_out[129]
    DIRECTION OUTPUT ;
    USE SIGNAL ;
    SHAPE ABUTMENT ;
    PORT
      LAYER met2 ;
      RECT 536.750 948.860 536.890 949.280 ;
    END
  END r0_rd_out[129]
  PIN rw0_addr_in[0]
    DIRECTION INPUT ;
    USE SIGNAL ;
    SHAPE ABUTMENT ;
    PORT
      LAYER met3 ;
      RECT 0.000 766.890 0.900 767.190 ;
    END
  END rw0_addr_in[0]
  PIN rw0_addr_in[1]
    DIRECTION INPUT ;
    USE SIGNAL ;
    SHAPE ABUTMENT ;
    PORT
      LAYER met3 ;
      RECT 0.000 790.010 0.900 790.310 ;
    END
  END rw0_addr_in[1]
  PIN rw0_addr_in[2]
    DIRECTION INPUT ;
    USE SIGNAL ;
    SHAPE ABUTMENT ;
    PORT
      LAYER met3 ;
      RECT 0.000 813.130 0.900 813.430 ;
    END
  END rw0_addr_in[2]
  PIN rw0_addr_in[3]
    DIRECTION INPUT ;
    USE SIGNAL ;
    SHAPE ABUTMENT ;
    PORT
      LAYER met3 ;
      RECT 0.000 836.250 0.900 836.550 ;
    END
  END rw0_addr_in[3]
  PIN rw0_addr_in[4]
    DIRECTION INPUT ;
    USE SIGNAL ;
    SHAPE ABUTMENT ;
    PORT
      LAYER met3 ;
      RECT 590.660 743.770 591.560 744.070 ;
    END
  END rw0_addr_in[4]
  PIN rw0_addr_in[5]
    DIRECTION INPUT ;
    USE SIGNAL ;
    SHAPE ABUTMENT ;
    PORT
      LAYER met3 ;
      RECT 590.660 766.890 591.560 767.190 ;
    END
  END rw0_addr_in[5]
  PIN rw0_addr_in[6]
    DIRECTION INPUT ;
    USE SIGNAL ;
    SHAPE ABUTMENT ;
    PORT
      LAYER met3 ;
      RECT 590.660 790.010 591.560 790.310 ;
    END
  END rw0_addr_in[6]
  PIN r0_addr_in[0]
    DIRECTION INPUT ;
    USE SIGNAL ;
    SHAPE ABUTMENT ;
    PORT
      LAYER met3 ;
      RECT 0.000 859.370 0.900 859.670 ;
    END
  END r0_addr_in[0]
  PIN r0_addr_in[1]
    DIRECTION INPUT ;
    USE SIGNAL ;
    SHAPE ABUTMENT ;
    PORT
      LAYER met3 ;
      RECT 0.000 882.490 0.900 882.790 ;
    END
  END r0_addr_in[1]
  PIN r0_addr_in[2]
    DIRECTION INPUT ;
    USE SIGNAL ;
    SHAPE ABUTMENT ;
    PORT
      LAYER met3 ;
      RECT 0.000 905.610 0.900 905.910 ;
    END
  END r0_addr_in[2]
  PIN r0_addr_in[3]
    DIRECTION INPUT ;
    USE SIGNAL ;
    SHAPE ABUTMENT ;
    PORT
      LAYER met3 ;
      RECT 0.000 928.730 0.900 929.030 ;
    END
  END r0_addr_in[3]
  PIN r0_addr_in[4]
    DIRECTION INPUT ;
    USE SIGNAL ;
    SHAPE ABUTMENT ;
    PORT
      LAYER met3 ;
      RECT 590.660 813.130 591.560 813.430 ;
    END
  END r0_addr_in[4]
  PIN r0_addr_in[5]
    DIRECTION INPUT ;
    USE SIGNAL ;
    SHAPE ABUTMENT ;
    PORT
      LAYER met3 ;
      RECT 590.660 836.250 591.560 836.550 ;
    END
  END r0_addr_in[5]
  PIN r0_addr_in[6]
    DIRECTION INPUT ;
    USE SIGNAL ;
    SHAPE ABUTMENT ;
    PORT
      LAYER met3 ;
      RECT 590.660 859.370 591.560 859.670 ;
    END
  END r0_addr_in[6]
  PIN rw0_we_in
    DIRECTION INPUT ;
    USE SIGNAL ;
    SHAPE ABUTMENT ;
    PORT
      LAYER met2 ;
      RECT 540.890 948.860 541.030 949.280 ;
    END
  END rw0_we_in
  PIN rw0_ce_in
    DIRECTION INPUT ;
    USE SIGNAL ;
    SHAPE ABUTMENT ;
    PORT
      LAYER met2 ;
      RECT 545.030 948.860 545.170 949.280 ;
    END
  END rw0_ce_in
  PIN rw0_clk
    DIRECTION INPUT ;
    USE SIGNAL ;
    SHAPE ABUTMENT ;
    PORT
      LAYER met2 ;
      RECT 549.170 948.860 549.310 949.280 ;
    END
  END rw0_clk
  PIN r0_ce_in
    DIRECTION INPUT ;
    USE SIGNAL ;
    SHAPE ABUTMENT ;
    PORT
      LAYER met2 ;
      RECT 553.310 948.860 553.450 949.280 ;
    END
  END r0_ce_in
  PIN r0_clk
    DIRECTION INPUT ;
    USE SIGNAL ;
    SHAPE ABUTMENT ;
    PORT
      LAYER met2 ;
      RECT 557.450 948.860 557.590 949.280 ;
    END
  END r0_clk
  PIN VSS
    DIRECTION INOUT ;
    USE GROUND ;
    PORT
      LAYER met4 ;
      RECT 2.160 4.080 3.360 945.200 ;
      RECT 13.040 4.080 14.240 945.200 ;
      RECT 23.920 4.080 25.120 945.200 ;
      RECT 34.800 4.080 36.000 945.200 ;
      RECT 45.680 4.080 46.880 945.200 ;
      RECT 56.560 4.080 57.760 945.200 ;
      RECT 67.440 4.080 68.640 945.200 ;
      RECT 78.320 4.080 79.520 945.200 ;
      RECT 89.200 4.080 90.400 945.200 ;
      RECT 100.080 4.080 101.280 945.200 ;
      RECT 110.960 4.080 112.160 945.200 ;
      RECT 121.840 4.080 123.040 945.200 ;
      RECT 132.720 4.080 133.920 945.200 ;
      RECT 143.600 4.080 144.800 945.200 ;
      RECT 154.480 4.080 155.680 945.200 ;
      RECT 165.360 4.080 166.560 945.200 ;
      RECT 176.240 4.080 177.440 945.200 ;
      RECT 187.120 4.080 188.320 945.200 ;
      RECT 198.000 4.080 199.200 945.200 ;
      RECT 208.880 4.080 210.080 945.200 ;
      RECT 219.760 4.080 220.960 945.200 ;
      RECT 230.640 4.080 231.840 945.200 ;
      RECT 241.520 4.080 242.720 945.200 ;
      RECT 252.400 4.080 253.600 945.200 ;
      RECT 263.280 4.080 264.480 945.200 ;
      RECT 274.160 4.080 275.360 945.200 ;
      RECT 285.040 4.080 286.240 945.200 ;
      RECT 295.920 4.080 297.120 945.200 ;
      RECT 306.800 4.080 308.000 945.200 ;
      RECT 317.680 4.080 318.880 945.200 ;
      RECT 328.560 4.080 329.760 945.200 ;
      RECT 339.440 4.080 340.640 945.200 ;
      RECT 350.320 4.080 351.520 945.200 ;
      RECT 361.200 4.080 362.400 945.200 ;
      RECT 372.080 4.080 373.280 945.200 ;
      RECT 382.960 4.080 384.160 945.200 ;
      RECT 393.840 4.080 395.040 945.200 ;
      RECT 404.720 4.080 405.920 945.200 ;
      RECT 415.600 4.080 416.800 945.200 ;
      RECT 426.480 4.080 427.680 945.200 ;
      RECT 437.360 4.080 438.560 945.200 ;
      RECT 448.240 4.080 449.440 945.200 ;
      RECT 459.120 4.080 460.320 945.200 ;
      RECT 470.000 4.080 471.200 945.200 ;
      RECT 480.880 4.080 482.080 945.200 ;
      RECT 491.760 4.080 492.960 945.200 ;
      RECT 502.640 4.080 503.840 945.200 ;
      RECT 513.520 4.080 514.720 945.200 ;
      RECT 524.400 4.080 525.600 945.200 ;
      RECT 535.280 4.080 536.480 945.200 ;
      RECT 546.160 4.080 547.360 945.200 ;
      RECT 557.040 4.080 558.240 945.200 ;
      RECT 567.920 4.080 569.120 945.200 ;
      RECT 578.800 4.080 580.000 945.200 ;
      RECT 589.680 4.080 590.880 945.200 ;
    END
  END VSS
  PIN VDD
    DIRECTION INOUT ;
    USE POWER ;
    PORT
      LAYER met4 ;
      RECT 7.600 4.080 8.800 945.200 ;
      RECT 18.480 4.080 19.680 945.200 ;
      RECT 29.360 4.080 30.560 945.200 ;
      RECT 40.240 4.080 41.440 945.200 ;
      RECT 51.120 4.080 52.320 945.200 ;
      RECT 62.000 4.080 63.200 945.200 ;
      RECT 72.880 4.080 74.080 945.200 ;
      RECT 83.760 4.080 84.960 945.200 ;
      RECT 94.640 4.080 95.840 945.200 ;
      RECT 105.520 4.080 106.720 945.200 ;
      RECT 116.400 4.080 117.600 945.200 ;
      RECT 127.280 4.080 128.480 945.200 ;
      RECT 138.160 4.080 139.360 945.200 ;
      RECT 149.040 4.080 150.240 945.200 ;
      RECT 159.920 4.080 161.120 945.200 ;
      RECT 170.800 4.080 172.000 945.200 ;
      RECT 181.680 4.080 182.880 945.200 ;
      RECT 192.560 4.080 193.760 945.200 ;
      RECT 203.440 4.080 204.640 945.200 ;
      RECT 214.320 4.080 215.520 945.200 ;
      RECT 225.200 4.080 226.400 945.200 ;
      RECT 236.080 4.080 237.280 945.200 ;
      RECT 246.960 4.080 248.160 945.200 ;
      RECT 257.840 4.080 259.040 945.200 ;
      RECT 268.720 4.080 269.920 945.200 ;
      RECT 279.600 4.080 280.800 945.200 ;
      RECT 290.480 4.080 291.680 945.200 ;
      RECT 301.360 4.080 302.560 945.200 ;
      RECT 312.240 4.080 313.440 945.200 ;
      RECT 323.120 4.080 324.320 945.200 ;
      RECT 334.000 4.080 335.200 945.200 ;
      RECT 344.880 4.080 346.080 945.200 ;
      RECT 355.760 4.080 356.960 945.200 ;
      RECT 366.640 4.080 367.840 945.200 ;
      RECT 377.520 4.080 378.720 945.200 ;
      RECT 388.400 4.080 389.600 945.200 ;
      RECT 399.280 4.080 400.480 945.200 ;
      RECT 410.160 4.080 411.360 945.200 ;
      RECT 421.040 4.080 422.240 945.200 ;
      RECT 431.920 4.080 433.120 945.200 ;
      RECT 442.800 4.080 444.000 945.200 ;
      RECT 453.680 4.080 454.880 945.200 ;
      RECT 464.560 4.080 465.760 945.200 ;
      RECT 475.440 4.080 476.640 945.200 ;
      RECT 486.320 4.080 487.520 945.200 ;
      RECT 497.200 4.080 498.400 945.200 ;
      RECT 508.080 4.080 509.280 945.200 ;
      RECT 518.960 4.080 520.160 945.200 ;
      RECT 529.840 4.080 531.040 945.200 ;
      RECT 540.720 4.080 541.920 945.200 ;
      RECT 551.600 4.080 552.800 945.200 ;
      RECT 562.480 4.080 563.680 945.200 ;
      RECT 573.360 4.080 574.560 945.200 ;
      RECT 584.240 4.080 585.440 945.200 ;
    END
  END VDD
  OBS
    LAYER met1 ;
    RECT 0 0 591.560 949.280 ;
    LAYER met2 ;
    RECT 0 0 591.560 949.280 ;
    LAYER met3 ;
    RECT 0 0 591.560 949.280 ;
    LAYER met4 ;
    RECT 0 0 591.560 949.280 ;
  END
END fakeram_1rw1r_130w128d_sram

END LIBRARY
